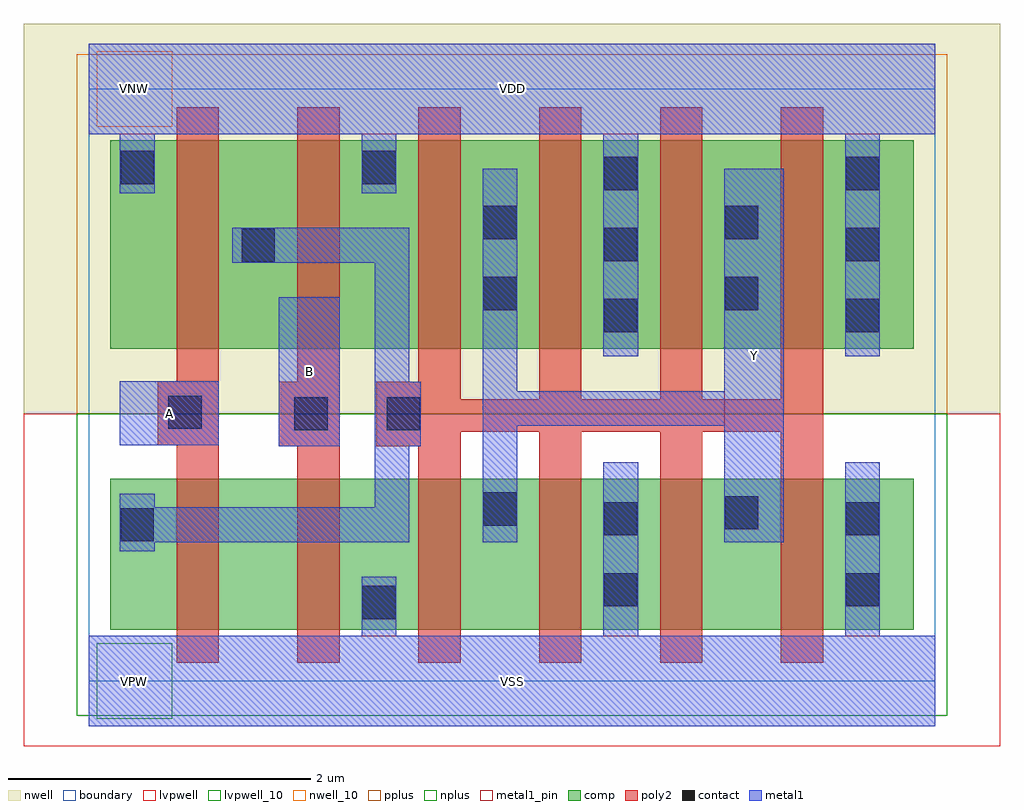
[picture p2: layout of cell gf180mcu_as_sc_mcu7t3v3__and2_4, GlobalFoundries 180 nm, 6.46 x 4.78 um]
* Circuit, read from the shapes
.subckt gf180mcu_as_sc_mcu7t3v3__and2_4 A B VDD VNW VSS Y
XM1 n1 A n2 VSUBS nfet_03v3 w=1u l=0.28u
XM2 VSS B n1 VSUBS nfet_03v3 w=1u l=0.28u
XM3 Y n2 VSS VSUBS nfet_03v3 w=1u l=0.28u m=4
XM4 n2 A VDD VNW pfet_03v3 w=1.38u l=0.28u
XM5 VDD B n2 VNW pfet_03v3 w=1.38u l=0.28u
XM6 Y n2 VDD VNW pfet_03v3 w=1.38u l=0.28u m=4
.ends

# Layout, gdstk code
import gdstk
lib = gdstk.Library(unit=1e-6, precision=1e-09)
def R(c, l, rs):  # rectangles x0, y0, x1, y1
    for r in rs: c.add(gdstk.rectangle(r[:2], r[2:], *l))
boundary = (0, 0)
nwell = (21, 0)
nwell_10 = (21, 10)
comp = (22, 0)
poly2 = (30, 0)
pplus = (31, 0)
nplus = (32, 0)
contact = (33, 0)
metal1 = (34, 0)
metal1_pin = (34, 10)
lvpwell = (204, 0)
lvpwell_10 = (204, 10)

gf180mcu_as_sc_mcu7t3v3_ = lib.new_cell('gf180mcu_as_sc_mcu7t3v3__and2_4')
R(gf180mcu_as_sc_mcu7t3v3_, boundary, [(0,0,5.6,3.92), (0,0,5.6,3.92)])
R(gf180mcu_as_sc_mcu7t3v3_, nwell, [(-0.43,1.77,6.03,4.35), (-0.43,1.77,6.03,4.35)])
R(gf180mcu_as_sc_mcu7t3v3_, nwell_10, [(0.05,3.67,0.55,4.17), (0.05,3.67,0.55,4.17)])
R(gf180mcu_as_sc_mcu7t3v3_, comp, [(0.14,0.34,5.46,1.34), (0.14,0.34,5.46,1.34), (0.14,2.2,5.46,3.58), (0.14,2.2,5.46,3.58)])
R(gf180mcu_as_sc_mcu7t3v3_, poly2, [(0.58,0.12,0.86,1.56), (0.58,0.12,0.86,1.56), (1.38,0.12,1.66,1.555), (1.38,0.12,1.66,1.555), (2.18,0.12,2.46,1.555), (2.18,0.12,2.46,1.555), (2.98,0.12,3.26,1.65), (2.98,0.12,3.26,1.65), (3.78,0.12,4.06,1.65), (3.78,0.12,4.06,1.65), (4.58,0.12,4.86,1.65), (4.58,0.12,4.86,1.65), (1.255,1.555,1.66,1.98), (1.255,1.555,1.66,1.98), (1.9,1.555,2.46,1.65), (1.9,1.555,2.46,1.65), (0.455,1.56,0.86,1.985), (0.455,1.56,0.86,1.985), (1.9,1.65,4.86,1.865), (1.9,1.65,4.86,1.865), (1.9,1.865,2.46,1.98), (1.9,1.865,2.46,1.98), (2.98,1.865,3.26,3.8), (2.98,1.865,3.26,3.8), (3.78,1.865,4.06,3.8), (3.78,1.865,4.06,3.8), (4.58,1.865,4.86,3.8), (4.58,1.865,4.86,3.8), (1.38,1.98,1.66,3.8), (1.38,1.98,1.66,3.8), (2.18,1.98,2.46,3.8), (2.18,1.98,2.46,3.8), (0.58,1.985,0.86,3.8), (0.58,1.985,0.86,3.8)])
R(gf180mcu_as_sc_mcu7t3v3_, pplus, [(-0.08,1.77,5.68,4.15), (-0.08,1.77,5.68,4.15), (0.35,1.97,5.09,2.04), (0.35,1.97,5.09,2.04), (-0.02,2.04,5.62,3.74), (-0.02,2.04,5.62,3.74), (0.35,3.74,5.09,3.81), (0.35,3.74,5.09,3.81)])
R(gf180mcu_as_sc_mcu7t3v3_, nplus, [(-0.08,-0.23,5.68,1.77), (-0.08,-0.23,5.68,1.77), (-0.08,-0.23,5.68,1.77), (-0.08,-0.23,5.68,1.77)])
R(gf180mcu_as_sc_mcu7t3v3_, contact, [(1.81,0.41,2.03,0.63), (1.81,0.41,2.03,0.63), (3.41,0.495,3.63,0.715), (3.41,0.495,3.63,0.715), (5.01,0.495,5.23,0.715), (5.01,0.495,5.23,0.715), (0.21,0.925,0.43,1.145), (0.21,0.925,0.43,1.145), (3.41,0.965,3.63,1.185), (3.41,0.965,3.63,1.185), (5.01,0.965,5.23,1.185), (5.01,0.965,5.23,1.185), (4.21,1.005,4.43,1.225), (4.21,1.005,4.43,1.225), (2.61,1.03,2.83,1.25), (2.61,1.03,2.83,1.25), (1.36,1.66,1.58,1.88), (1.36,1.66,1.58,1.88), (1.97,1.66,2.19,1.88), (1.97,1.66,2.19,1.88), (0.525,1.67,0.745,1.89), (0.525,1.67,0.745,1.89), (3.41,2.31,3.63,2.53), (3.41,2.31,3.63,2.53), (5.01,2.31,5.23,2.53), (5.01,2.31,5.23,2.53), (2.61,2.455,2.83,2.675), (2.61,2.455,2.83,2.675), (4.21,2.455,4.43,2.675), (4.21,2.455,4.43,2.675), (1.01,2.775,1.23,2.995), (1.01,2.775,1.23,2.995), (3.41,2.78,3.63,3), (3.41,2.78,3.63,3), (5.01,2.78,5.23,3), (5.01,2.78,5.23,3), (2.61,2.925,2.83,3.145), (2.61,2.925,2.83,3.145), (4.21,2.925,4.43,3.145), (4.21,2.925,4.43,3.145), (3.41,3.25,3.63,3.47), (3.41,3.25,3.63,3.47), (5.01,3.25,5.23,3.47), (5.01,3.25,5.23,3.47), (0.21,3.29,0.43,3.51), (0.21,3.29,0.43,3.51), (1.81,3.29,2.03,3.51), (1.81,3.29,2.03,3.51)])
R(gf180mcu_as_sc_mcu7t3v3_, metal1, [(0,-0.3,5.6,0.3), (0,-0.3,5.6,0.3), (1.805,0.3,2.035,0.69), (1.805,0.3,2.035,0.69), (3.405,0.3,3.635,1.45), (3.405,0.3,3.635,1.45), (5.005,0.3,5.235,1.45), (5.005,0.3,5.235,1.45), (0.205,0.86,0.435,0.92), (0.205,0.86,0.435,0.92), (0.205,0.92,2.12,1.15), (0.205,0.92,2.12,1.15), (2.605,0.92,2.835,1.69), (2.605,0.92,2.835,1.69), (4.205,0.92,4.6,1.69), (4.205,0.92,4.6,1.69), (0.205,1.15,0.435,1.24), (0.205,1.15,0.435,1.24), (1.89,1.15,2.12,1.555), (1.89,1.15,2.12,1.555), (1.255,1.555,1.66,2.54), (1.255,1.555,1.66,2.54), (1.89,1.555,2.195,1.98), (1.89,1.555,2.195,1.98), (0.205,1.56,0.86,1.985), (0.205,1.56,0.86,1.985), (2.605,1.69,4.6,1.92), (2.605,1.69,4.6,1.92), (2.605,1.92,2.835,3.39), (2.605,1.92,2.835,3.39), (4.205,1.92,4.6,3.39), (4.205,1.92,4.6,3.39), (1.89,1.98,2.12,2.77), (1.89,1.98,2.12,2.77), (3.405,2.15,3.635,3.62), (3.405,2.15,3.635,3.62), (5.005,2.15,5.235,3.62), (5.005,2.15,5.235,3.62), (0.95,2.77,2.12,3), (0.95,2.77,2.12,3), (0.205,3.23,0.435,3.62), (0.205,3.23,0.435,3.62), (1.805,3.23,2.035,3.62), (1.805,3.23,2.035,3.62), (0,3.62,5.6,4.22), (0,3.62,5.6,4.22)])
R(gf180mcu_as_sc_mcu7t3v3_, metal1_pin, [(0,-0.3,5.6,0.3), (0,-0.3,5.6,0.3), (4.205,0.92,4.6,3.39), (4.205,0.92,4.6,3.39), (1.255,1.555,1.66,2.54), (1.255,1.555,1.66,2.54), (0.205,1.56,0.86,1.985), (0.205,1.56,0.86,1.985), (0,3.62,5.6,4.22), (0,3.62,5.6,4.22)])
R(gf180mcu_as_sc_mcu7t3v3_, lvpwell, [(-0.43,-0.43,6.03,1.77), (-0.43,-0.43,6.03,1.77)])
R(gf180mcu_as_sc_mcu7t3v3_, lvpwell_10, [(0.05,-0.25,0.55,0.25), (0.05,-0.25,0.55,0.25)])
gf180mcu_as_sc_mcu7t3v3_.add(gdstk.Label('VDD', (2.8,3.92), layer=34, texttype=10))
gf180mcu_as_sc_mcu7t3v3_.add(gdstk.Label('VSS', (2.8,0), layer=34, texttype=10))
gf180mcu_as_sc_mcu7t3v3_.add(gdstk.Label('B', (1.457,2.047), layer=34, texttype=10))
gf180mcu_as_sc_mcu7t3v3_.add(gdstk.Label('A', (0.532,1.772), layer=34, texttype=10))
gf180mcu_as_sc_mcu7t3v3_.add(gdstk.Label('Y', (4.402,2.155), layer=34, texttype=10))
gf180mcu_as_sc_mcu7t3v3_.add(gdstk.Label('VDD', (2.8,3.92), layer=34, texttype=10))
gf180mcu_as_sc_mcu7t3v3_.add(gdstk.Label('VSS', (2.8,0), layer=34, texttype=10))
gf180mcu_as_sc_mcu7t3v3_.add(gdstk.Label('B', (1.457,2.047), layer=34, texttype=10))
gf180mcu_as_sc_mcu7t3v3_.add(gdstk.Label('A', (0.532,1.772), layer=34, texttype=10))
gf180mcu_as_sc_mcu7t3v3_.add(gdstk.Label('Y', (4.402,2.155), layer=34, texttype=10))
gf180mcu_as_sc_mcu7t3v3_.add(gdstk.Label('VNW', (0.3,3.92), layer=21, texttype=10))
gf180mcu_as_sc_mcu7t3v3_.add(gdstk.Label('VNW', (0.3,3.92), layer=21, texttype=10))
gf180mcu_as_sc_mcu7t3v3_.add(gdstk.Label('VPW', (0.3,0), layer=204, texttype=10))
gf180mcu_as_sc_mcu7t3v3_.add(gdstk.Label('VPW', (0.3,0), layer=204, texttype=10))

lib.write_gds('gf180mcu_as_sc_mcu7t3v3__and2_4.gds')
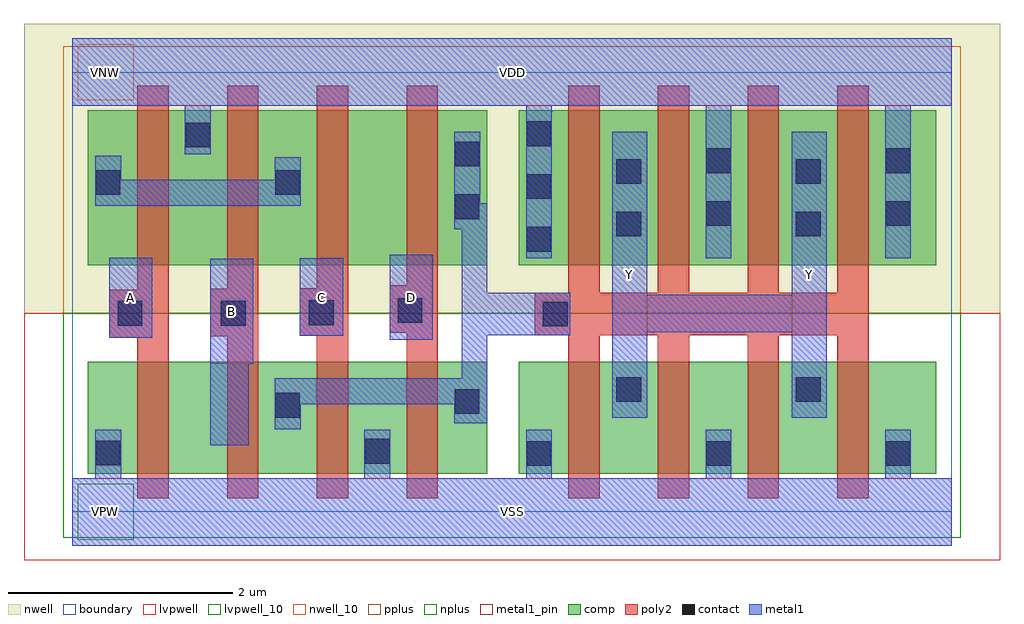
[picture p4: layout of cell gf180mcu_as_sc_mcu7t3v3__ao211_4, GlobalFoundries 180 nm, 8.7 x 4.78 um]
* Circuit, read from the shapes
.subckt gf180mcu_as_sc_mcu7t3v3__ao211_4 A B C D VDD VNW VSS Y
XM1 n1 A VSS VSUBS nfet_03v3 w=1u l=0.28u
XM2 n2 B n1 VSUBS nfet_03v3 w=1u l=0.28u
XM3 VSS C n2 VSUBS nfet_03v3 w=1u l=0.28u
XM4 n2 D VSS VSUBS nfet_03v3 w=1u l=0.28u
XM5 Y n2 VSS VSUBS nfet_03v3 w=1u l=0.28u m=4
XM6 VDD A n3 VNW pfet_03v3 w=1.38u l=0.28u
XM7 n3 B VDD VNW pfet_03v3 w=1.38u l=0.28u
XM8 n4 C n3 VNW pfet_03v3 w=1.38u l=0.28u
XM9 n2 D n4 VNW pfet_03v3 w=1.38u l=0.28u
XM10 Y n2 VDD VNW pfet_03v3 w=1.38u l=0.28u m=4
.ends

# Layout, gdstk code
import gdstk
lib = gdstk.Library(unit=1e-6, precision=1e-09)
def R(c, l, rs):  # rectangles x0, y0, x1, y1
    for r in rs: c.add(gdstk.rectangle(r[:2], r[2:], *l))
boundary = (0, 0)
nwell = (21, 0)
nwell_10 = (21, 10)
comp = (22, 0)
poly2 = (30, 0)
pplus = (31, 0)
nplus = (32, 0)
contact = (33, 0)
metal1 = (34, 0)
metal1_pin = (34, 10)
lvpwell = (204, 0)
lvpwell_10 = (204, 10)

gf180mcu_as_sc_mcu7t3v3_ = lib.new_cell('gf180mcu_as_sc_mcu7t3v3__ao211_4')
R(gf180mcu_as_sc_mcu7t3v3_, boundary, [(0,0,7.84,3.92), (0,0,7.84,3.92)])
R(gf180mcu_as_sc_mcu7t3v3_, nwell, [(-0.43,1.77,8.27,4.35), (-0.43,1.77,8.27,4.35)])
R(gf180mcu_as_sc_mcu7t3v3_, nwell_10, [(0.05,3.67,0.55,4.17), (0.05,3.67,0.55,4.17)])
R(gf180mcu_as_sc_mcu7t3v3_, comp, [(0.14,0.34,3.7,1.34), (0.14,0.34,3.7,1.34), (3.98,0.34,7.7,1.34), (3.98,0.34,7.7,1.34), (0.14,2.2,3.7,3.58), (0.14,2.2,3.7,3.58), (3.98,2.2,7.7,3.58), (3.98,2.2,7.7,3.58)])
R(gf180mcu_as_sc_mcu7t3v3_, poly2, [(0.58,0.12,0.86,1.55), (0.58,0.12,0.86,1.55), (1.38,0.12,1.66,1.565), (1.38,0.12,1.66,1.565), (2.18,0.12,2.46,1.57), (2.18,0.12,2.46,1.57), (2.98,0.12,3.26,1.595), (2.98,0.12,3.26,1.595), (4.42,0.12,4.7,1.575), (4.42,0.12,4.7,1.575), (5.22,0.12,5.5,1.575), (5.22,0.12,5.5,1.575), (6.02,0.12,6.3,1.575), (6.02,0.12,6.3,1.575), (6.82,0.12,7.1,1.575), (6.82,0.12,7.1,1.575), (0.33,1.55,0.86,1.98), (0.33,1.55,0.86,1.98), (1.23,1.565,1.66,1.99), (1.23,1.565,1.66,1.99), (2.03,1.57,2.46,1.995), (2.03,1.57,2.46,1.995), (4.125,1.575,7.1,1.955), (4.125,1.575,7.1,1.955), (2.83,1.595,3.26,2.02), (2.83,1.595,3.26,2.02), (4.42,1.955,4.7,3.8), (4.42,1.955,4.7,3.8), (5.22,1.955,5.5,3.8), (5.22,1.955,5.5,3.8), (6.02,1.955,6.3,3.8), (6.02,1.955,6.3,3.8), (6.82,1.955,7.1,3.8), (6.82,1.955,7.1,3.8), (0.58,1.98,0.86,3.8), (0.58,1.98,0.86,3.8), (1.38,1.99,1.66,3.8), (1.38,1.99,1.66,3.8), (2.18,1.995,2.46,3.8), (2.18,1.995,2.46,3.8), (2.98,2.02,3.26,3.8), (2.98,2.02,3.26,3.8)])
R(gf180mcu_as_sc_mcu7t3v3_, pplus, [(-0.08,1.77,7.92,4.15), (-0.08,1.77,7.92,4.15), (0.35,1.97,3.49,2.04), (0.35,1.97,3.49,2.04), (4.19,1.97,7.33,2.04), (4.19,1.97,7.33,2.04), (-0.02,2.04,7.86,3.74), (-0.02,2.04,7.86,3.74), (0.35,3.74,3.49,3.81), (0.35,3.74,3.49,3.81), (4.19,3.74,7.33,3.81), (4.19,3.74,7.33,3.81)])
R(gf180mcu_as_sc_mcu7t3v3_, nplus, [(-0.08,-0.23,7.92,1.77), (-0.08,-0.23,7.92,1.77), (-0.08,-0.23,7.92,1.77), (-0.08,-0.23,7.92,1.77)])
R(gf180mcu_as_sc_mcu7t3v3_, contact, [(4.05,0.41,4.27,0.63), (4.05,0.41,4.27,0.63), (5.65,0.41,5.87,0.63), (5.65,0.41,5.87,0.63), (7.25,0.41,7.47,0.63), (7.25,0.41,7.47,0.63), (0.21,0.415,0.43,0.635), (0.21,0.415,0.43,0.635), (2.61,0.43,2.83,0.65), (2.61,0.43,2.83,0.65), (1.81,0.84,2.03,1.06), (1.81,0.84,2.03,1.06), (3.41,0.875,3.63,1.095), (3.41,0.875,3.63,1.095), (4.85,0.98,5.07,1.2), (4.85,0.98,5.07,1.2), (6.45,0.98,6.67,1.2), (6.45,0.98,6.67,1.2), (4.195,1.655,4.415,1.875), (4.195,1.655,4.415,1.875), (0.405,1.66,0.625,1.88), (0.405,1.66,0.625,1.88), (1.325,1.66,1.545,1.88), (1.325,1.66,1.545,1.88), (2.11,1.665,2.33,1.885), (2.11,1.665,2.33,1.885), (2.9,1.685,3.12,1.905), (2.9,1.685,3.12,1.905), (4.05,2.32,4.27,2.54), (4.05,2.32,4.27,2.54), (4.85,2.455,5.07,2.675), (4.85,2.455,5.07,2.675), (6.45,2.455,6.67,2.675), (6.45,2.455,6.67,2.675), (5.65,2.55,5.87,2.77), (5.65,2.55,5.87,2.77), (7.25,2.55,7.47,2.77), (7.25,2.55,7.47,2.77), (3.41,2.61,3.63,2.83), (3.41,2.61,3.63,2.83), (4.05,2.79,4.27,3.01), (4.05,2.79,4.27,3.01), (0.21,2.825,0.43,3.045), (0.21,2.825,0.43,3.045), (1.81,2.825,2.03,3.045), (1.81,2.825,2.03,3.045), (4.85,2.925,5.07,3.145), (4.85,2.925,5.07,3.145), (6.45,2.925,6.67,3.145), (6.45,2.925,6.67,3.145), (5.65,3.02,5.87,3.24), (5.65,3.02,5.87,3.24), (7.25,3.02,7.47,3.24), (7.25,3.02,7.47,3.24), (3.41,3.08,3.63,3.3), (3.41,3.08,3.63,3.3), (1.01,3.25,1.23,3.47), (1.01,3.25,1.23,3.47), (4.05,3.26,4.27,3.48), (4.05,3.26,4.27,3.48)])
R(gf180mcu_as_sc_mcu7t3v3_, metal1, [(0,-0.3,7.84,0.3), (0,-0.3,7.84,0.3), (0.205,0.3,0.435,0.73), (0.205,0.3,0.435,0.73), (2.605,0.3,2.835,0.73), (2.605,0.3,2.835,0.73), (4.045,0.3,4.275,0.73), (4.045,0.3,4.275,0.73), (5.645,0.3,5.875,0.73), (5.645,0.3,5.875,0.73), (7.245,0.3,7.475,0.73), (7.245,0.3,7.475,0.73), (1.23,0.595,1.575,1.32), (1.23,0.595,1.575,1.32), (1.805,0.735,2.035,0.96), (1.805,0.735,2.035,0.96), (3.405,0.79,3.7,0.96), (3.405,0.79,3.7,0.96), (4.815,0.84,5.125,1.6), (4.815,0.84,5.125,1.6), (6.415,0.84,6.725,1.6), (6.415,0.84,6.725,1.6), (1.805,0.96,3.7,1.19), (1.805,0.96,3.7,1.19), (3.47,1.19,3.7,1.575), (3.47,1.19,3.7,1.575), (1.23,1.32,1.615,2.255), (1.23,1.32,1.615,2.255), (2.83,1.535,3.215,2.29), (2.83,1.535,3.215,2.29), (0.33,1.55,0.715,2.265), (0.33,1.55,0.715,2.265), (2.03,1.57,2.415,2.26), (2.03,1.57,2.415,2.26), (3.47,1.575,4.44,1.955), (3.47,1.575,4.44,1.955), (4.815,1.6,6.725,1.935), (4.815,1.6,6.725,1.935), (4.815,1.935,5.125,3.39), (4.815,1.935,5.125,3.39), (6.415,1.935,6.725,3.39), (6.415,1.935,6.725,3.39), (3.47,1.955,3.7,2.52), (3.47,1.955,3.7,2.52), (4.045,2.26,4.275,3.62), (4.045,2.26,4.275,3.62), (5.645,2.26,5.875,3.62), (5.645,2.26,5.875,3.62), (7.245,2.26,7.475,3.62), (7.245,2.26,7.475,3.62), (3.405,2.52,3.7,2.75), (3.405,2.52,3.7,2.75), (0.205,2.73,2.035,2.96), (0.205,2.73,2.035,2.96), (3.405,2.75,3.635,3.39), (3.405,2.75,3.635,3.39), (0.205,2.96,0.435,3.175), (0.205,2.96,0.435,3.175), (1.805,2.96,2.035,3.16), (1.805,2.96,2.035,3.16), (1.005,3.19,1.235,3.62), (1.005,3.19,1.235,3.62), (0,3.62,7.84,4.22), (0,3.62,7.84,4.22)])
R(gf180mcu_as_sc_mcu7t3v3_, metal1_pin, [(0,-0.3,7.84,0.3), (0,-0.3,7.84,0.3), (4.815,0.84,5.125,3.39), (4.815,0.84,5.125,3.39), (6.415,0.84,6.725,3.39), (6.415,0.84,6.725,3.39), (1.23,1.32,1.615,2.255), (1.23,1.32,1.615,2.255), (2.83,1.535,3.215,2.29), (2.83,1.535,3.215,2.29), (0.33,1.55,0.715,2.265), (0.33,1.55,0.715,2.265), (2.03,1.57,2.415,2.26), (2.03,1.57,2.415,2.26), (0,3.62,7.84,4.22), (0,3.62,7.84,4.22)])
R(gf180mcu_as_sc_mcu7t3v3_, lvpwell, [(-0.43,-0.43,8.27,1.77), (-0.43,-0.43,8.27,1.77)])
R(gf180mcu_as_sc_mcu7t3v3_, lvpwell_10, [(0.05,-0.25,0.55,0.25), (0.05,-0.25,0.55,0.25)])
gf180mcu_as_sc_mcu7t3v3_.add(gdstk.Label('VDD', (3.92,3.92), layer=34, texttype=10))
gf180mcu_as_sc_mcu7t3v3_.add(gdstk.Label('VSS', (3.92,0), layer=34, texttype=10))
gf180mcu_as_sc_mcu7t3v3_.add(gdstk.Label('A', (0.522,1.907), layer=34, texttype=10))
gf180mcu_as_sc_mcu7t3v3_.add(gdstk.Label('B', (1.422,1.787), layer=34, texttype=10))
gf180mcu_as_sc_mcu7t3v3_.add(gdstk.Label('C', (2.222,1.915), layer=34, texttype=10))
gf180mcu_as_sc_mcu7t3v3_.add(gdstk.Label('D', (3.022,1.912), layer=34, texttype=10))
gf180mcu_as_sc_mcu7t3v3_.add(gdstk.Label('Y', (6.57,2.115), layer=34, texttype=10))
gf180mcu_as_sc_mcu7t3v3_.add(gdstk.Label('Y', (4.97,2.115), layer=34, texttype=10))
gf180mcu_as_sc_mcu7t3v3_.add(gdstk.Label('VDD', (3.92,3.92), layer=34, texttype=10))
gf180mcu_as_sc_mcu7t3v3_.add(gdstk.Label('VSS', (3.92,0), layer=34, texttype=10))
gf180mcu_as_sc_mcu7t3v3_.add(gdstk.Label('A', (0.522,1.907), layer=34, texttype=10))
gf180mcu_as_sc_mcu7t3v3_.add(gdstk.Label('B', (1.422,1.787), layer=34, texttype=10))
gf180mcu_as_sc_mcu7t3v3_.add(gdstk.Label('C', (2.222,1.915), layer=34, texttype=10))
gf180mcu_as_sc_mcu7t3v3_.add(gdstk.Label('D', (3.022,1.912), layer=34, texttype=10))
gf180mcu_as_sc_mcu7t3v3_.add(gdstk.Label('Y', (6.57,2.115), layer=34, texttype=10))
gf180mcu_as_sc_mcu7t3v3_.add(gdstk.Label('Y', (4.97,2.115), layer=34, texttype=10))
gf180mcu_as_sc_mcu7t3v3_.add(gdstk.Label('VNW', (0.3,3.92), layer=21, texttype=10))
gf180mcu_as_sc_mcu7t3v3_.add(gdstk.Label('VNW', (0.3,3.92), layer=21, texttype=10))
gf180mcu_as_sc_mcu7t3v3_.add(gdstk.Label('VPW', (0.3,0), layer=204, texttype=10))
gf180mcu_as_sc_mcu7t3v3_.add(gdstk.Label('VPW', (0.3,0), layer=204, texttype=10))

lib.write_gds('gf180mcu_as_sc_mcu7t3v3__ao211_4.gds')
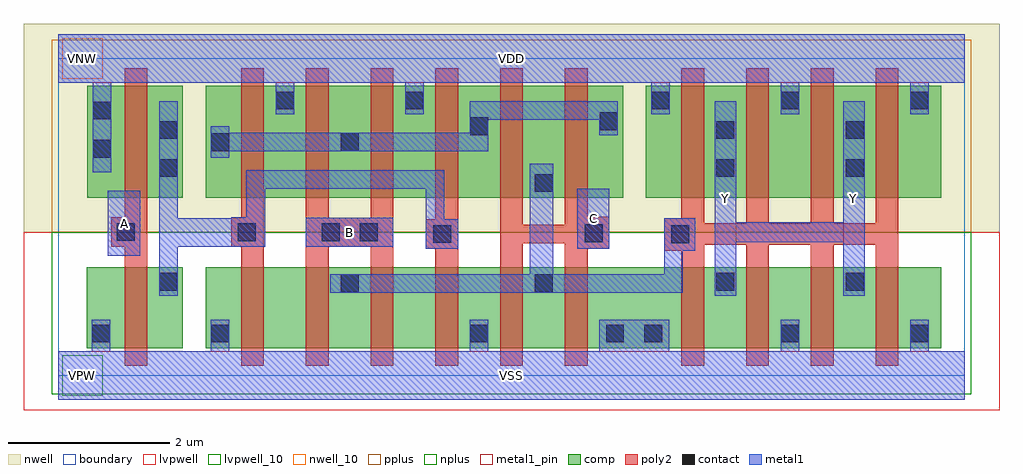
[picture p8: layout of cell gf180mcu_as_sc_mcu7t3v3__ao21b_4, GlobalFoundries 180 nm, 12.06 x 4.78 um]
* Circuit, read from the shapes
.subckt gf180mcu_as_sc_mcu7t3v3__ao21b_4 A B C VDD VNW VSS Y
XM1 n1 A VSS VSUBS nfet_03v3 w=1u l=0.28u
XM2 n2 n1 VSS VSUBS nfet_03v3 w=1u l=0.28u
XM3 n3 B n2 VSUBS nfet_03v3 w=1u l=0.28u
XM4 n4 B n3 VSUBS nfet_03v3 w=1u l=0.28u
XM5 VSS n1 n4 VSUBS nfet_03v3 w=1u l=0.28u
XM6 n3 C VSS VSUBS nfet_03v3 w=1u l=0.28u m=2
XM7 Y n3 VSS VSUBS nfet_03v3 w=1u l=0.28u m=4
XM8 n1 A VDD VNW pfet_03v3 w=1.38u l=0.28u
XM9 VDD n1 n5 VNW pfet_03v3 w=1.38u l=0.28u m=2
XM10 n5 B VDD VNW pfet_03v3 w=1.38u l=0.28u m=2
XM11 n3 C n5 VNW pfet_03v3 w=1.38u l=0.28u m=2
XM12 Y n3 VDD VNW pfet_03v3 w=1.38u l=0.28u m=4
.ends

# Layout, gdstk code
import gdstk
lib = gdstk.Library(unit=1e-6, precision=1e-09)
def R(c, l, rs):  # rectangles x0, y0, x1, y1
    for r in rs: c.add(gdstk.rectangle(r[:2], r[2:], *l))
boundary = (0, 0)
nwell = (21, 0)
nwell_10 = (21, 10)
comp = (22, 0)
poly2 = (30, 0)
pplus = (31, 0)
nplus = (32, 0)
contact = (33, 0)
metal1 = (34, 0)
metal1_pin = (34, 10)
lvpwell = (204, 0)
lvpwell_10 = (204, 10)

gf180mcu_as_sc_mcu7t3v3_ = lib.new_cell('gf180mcu_as_sc_mcu7t3v3__ao21b_4')
R(gf180mcu_as_sc_mcu7t3v3_, boundary, [(0,0,11.2,3.92), (0,0,11.2,3.92)])
R(gf180mcu_as_sc_mcu7t3v3_, nwell, [(-0.43,1.77,11.63,4.35), (-0.43,1.77,11.63,4.35)])
R(gf180mcu_as_sc_mcu7t3v3_, nwell_10, [(0.05,3.67,0.55,4.17), (0.05,3.67,0.55,4.17)])
R(gf180mcu_as_sc_mcu7t3v3_, comp, [(0.35,0.34,1.54,1.34), (0.35,0.34,1.54,1.34), (1.82,0.34,10.91,1.34), (1.82,0.34,10.91,1.34), (0.36,2.2,1.54,3.58), (0.36,2.2,1.54,3.58), (1.82,2.2,6.98,3.58), (1.82,2.2,6.98,3.58), (7.26,2.2,10.91,3.58), (7.26,2.2,10.91,3.58)])
R(gf180mcu_as_sc_mcu7t3v3_, poly2, [(0.82,0.12,1.1,1.595), (0.82,0.12,1.1,1.595), (2.26,0.12,2.54,1.59), (2.26,0.12,2.54,1.59), (3.06,0.12,3.34,1.59), (3.06,0.12,3.34,1.59), (3.86,0.12,4.14,1.59), (3.86,0.12,4.14,1.59), (4.66,0.12,4.94,1.57), (4.66,0.12,4.94,1.57), (5.46,0.12,5.74,1.635), (5.46,0.12,5.74,1.635), (6.26,0.12,6.54,1.565), (6.26,0.12,6.54,1.565), (7.7,0.12,7.98,1.545), (7.7,0.12,7.98,1.545), (8.5,0.12,8.78,1.62), (8.5,0.12,8.78,1.62), (9.3,0.12,9.58,1.62), (9.3,0.12,9.58,1.62), (10.1,0.12,10.38,1.62), (10.1,0.12,10.38,1.62), (7.485,1.545,7.98,1.62), (7.485,1.545,7.98,1.62), (6.26,1.565,6.805,1.635), (6.26,1.565,6.805,1.635), (4.54,1.57,4.945,1.93), (4.54,1.57,4.945,1.93), (2.135,1.59,2.54,1.95), (2.135,1.59,2.54,1.95), (3.06,1.59,4.14,1.95), (3.06,1.59,4.14,1.95), (0.655,1.595,1.1,1.955), (0.655,1.595,1.1,1.955), (7.485,1.62,10.38,1.885), (7.485,1.62,10.38,1.885), (5.46,1.635,6.805,1.865), (5.46,1.635,6.805,1.865), (5.46,1.865,5.74,3.8), (5.46,1.865,5.74,3.8), (6.26,1.865,6.805,1.96), (6.26,1.865,6.805,1.96), (7.485,1.885,7.98,1.945), (7.485,1.885,7.98,1.945), (8.5,1.885,8.78,3.8), (8.5,1.885,8.78,3.8), (9.3,1.885,9.58,3.8), (9.3,1.885,9.58,3.8), (10.1,1.885,10.38,3.8), (10.1,1.885,10.38,3.8), (4.66,1.93,4.94,3.8), (4.66,1.93,4.94,3.8), (7.7,1.945,7.98,3.8), (7.7,1.945,7.98,3.8), (2.26,1.95,2.54,3.8), (2.26,1.95,2.54,3.8), (3.06,1.95,3.34,3.8), (3.06,1.95,3.34,3.8), (3.86,1.95,4.14,3.8), (3.86,1.95,4.14,3.8), (0.82,1.955,1.1,3.8), (0.82,1.955,1.1,3.8), (6.26,1.96,6.54,3.8), (6.26,1.96,6.54,3.8)])
R(gf180mcu_as_sc_mcu7t3v3_, pplus, [(-0.08,1.77,11.28,4.15), (-0.08,1.77,11.28,4.15), (0.59,1.97,1.33,2.04), (0.59,1.97,1.33,2.04), (2.03,1.97,6.77,2.04), (2.03,1.97,6.77,2.04), (7.47,1.97,10.61,2.04), (7.47,1.97,10.61,2.04), (0.2,2.04,11.07,3.74), (0.2,2.04,11.07,3.74), (0.59,3.74,1.33,3.81), (0.59,3.74,1.33,3.81), (2.03,3.74,6.77,3.81), (2.03,3.74,6.77,3.81), (7.47,3.74,10.61,3.81), (7.47,3.74,10.61,3.81)])
R(gf180mcu_as_sc_mcu7t3v3_, nplus, [(-0.08,-0.23,11.28,1.77), (-0.08,-0.23,11.28,1.77), (-0.08,-0.23,11.28,1.77), (-0.08,-0.23,11.28,1.77)])
R(gf180mcu_as_sc_mcu7t3v3_, contact, [(0.42,0.41,0.64,0.63), (0.42,0.41,0.64,0.63), (1.89,0.41,2.11,0.63), (1.89,0.41,2.11,0.63), (5.09,0.41,5.31,0.63), (5.09,0.41,5.31,0.63), (6.77,0.41,6.99,0.63), (6.77,0.41,6.99,0.63), (7.24,0.41,7.46,0.63), (7.24,0.41,7.46,0.63), (8.93,0.41,9.15,0.63), (8.93,0.41,9.15,0.63), (10.53,0.41,10.75,0.63), (10.53,0.41,10.75,0.63), (3.49,1.03,3.71,1.25), (3.49,1.03,3.71,1.25), (5.89,1.03,6.11,1.25), (5.89,1.03,6.11,1.25), (1.25,1.05,1.47,1.27), (1.25,1.05,1.47,1.27), (8.13,1.05,8.35,1.27), (8.13,1.05,8.35,1.27), (9.73,1.05,9.95,1.27), (9.73,1.05,9.95,1.27), (7.575,1.635,7.795,1.855), (7.575,1.635,7.795,1.855), (4.635,1.64,4.855,1.86), (4.635,1.64,4.855,1.86), (6.505,1.65,6.725,1.87), (6.505,1.65,6.725,1.87), (2.22,1.66,2.44,1.88), (2.22,1.66,2.44,1.88), (3.255,1.66,3.475,1.88), (3.255,1.66,3.475,1.88), (3.725,1.66,3.945,1.88), (3.725,1.66,3.945,1.88), (0.725,1.665,0.945,1.885), (0.725,1.665,0.945,1.885), (5.89,2.27,6.11,2.49), (5.89,2.27,6.11,2.49), (1.25,2.455,1.47,2.675), (1.25,2.455,1.47,2.675), (8.13,2.455,8.35,2.675), (8.13,2.455,8.35,2.675), (9.73,2.455,9.95,2.675), (9.73,2.455,9.95,2.675), (0.43,2.695,0.65,2.915), (0.43,2.695,0.65,2.915), (1.89,2.775,2.11,2.995), (1.89,2.775,2.11,2.995), (3.49,2.775,3.71,2.995), (3.49,2.775,3.71,2.995), (1.25,2.925,1.47,3.145), (1.25,2.925,1.47,3.145), (8.13,2.925,8.35,3.145), (8.13,2.925,8.35,3.145), (9.73,2.925,9.95,3.145), (9.73,2.925,9.95,3.145), (5.09,2.97,5.31,3.19), (5.09,2.97,5.31,3.19), (6.69,3.035,6.91,3.255), (6.69,3.035,6.91,3.255), (0.43,3.165,0.65,3.385), (0.43,3.165,0.65,3.385), (2.69,3.29,2.91,3.51), (2.69,3.29,2.91,3.51), (4.29,3.29,4.51,3.51), (4.29,3.29,4.51,3.51), (7.33,3.29,7.55,3.51), (7.33,3.29,7.55,3.51), (8.93,3.29,9.15,3.51), (8.93,3.29,9.15,3.51), (10.53,3.29,10.75,3.51), (10.53,3.29,10.75,3.51)])
R(gf180mcu_as_sc_mcu7t3v3_, metal1, [(0,-0.3,11.2,0.3), (0,-0.3,11.2,0.3), (0.415,0.3,0.645,0.69), (0.415,0.3,0.645,0.69), (1.885,0.3,2.115,0.69), (1.885,0.3,2.115,0.69), (5.085,0.3,5.315,0.69), (5.085,0.3,5.315,0.69), (6.685,0.3,7.55,0.69), (6.685,0.3,7.55,0.69), (8.925,0.3,9.155,0.69), (8.925,0.3,9.155,0.69), (10.525,0.3,10.755,0.69), (10.525,0.3,10.755,0.69), (1.245,0.985,1.475,1.595), (1.245,0.985,1.475,1.595), (8.11,0.99,8.375,1.645), (8.11,0.99,8.375,1.645), (9.7,0.99,9.965,1.645), (9.7,0.99,9.965,1.645), (3.36,1.025,7.715,1.255), (3.36,1.025,7.715,1.255), (5.825,1.255,6.115,2.62), (5.825,1.255,6.115,2.62), (7.485,1.255,7.715,1.545), (7.485,1.255,7.715,1.545), (0.61,1.48,1.015,2.285), (0.61,1.48,1.015,2.285), (7.485,1.545,7.87,1.945), (7.485,1.545,7.87,1.945), (6.415,1.565,6.805,2.31), (6.415,1.565,6.805,2.31), (4.54,1.57,4.945,1.93), (4.54,1.57,4.945,1.93), (2.135,1.59,2.555,1.595), (2.135,1.59,2.555,1.595), (3.06,1.59,4.14,1.95), (3.06,1.59,4.14,1.95), (1.245,1.595,2.555,1.945), (1.245,1.595,2.555,1.945), (8.11,1.645,9.965,1.895), (8.11,1.645,9.965,1.895), (8.11,1.895,8.375,3.39), (8.11,1.895,8.375,3.39), (9.7,1.895,9.965,3.39), (9.7,1.895,9.965,3.39), (4.54,1.93,4.77,2.31), (4.54,1.93,4.77,2.31), (1.245,1.945,1.475,3.39), (1.245,1.945,1.475,3.39), (2.135,1.945,2.555,1.955), (2.135,1.945,2.555,1.955), (2.325,1.955,2.555,2.31), (2.325,1.955,2.555,2.31), (2.325,2.31,4.77,2.54), (2.325,2.31,4.77,2.54), (0.425,2.515,0.655,3.62), (0.425,2.515,0.655,3.62), (1.885,2.695,2.115,2.77), (1.885,2.695,2.115,2.77), (1.885,2.77,5.315,3), (1.885,2.77,5.315,3), (6.685,2.97,6.915,3.16), (6.685,2.97,6.915,3.16), (1.885,3,2.115,3.08), (1.885,3,2.115,3.08), (5.085,3,5.315,3.16), (5.085,3,5.315,3.16), (5.085,3.16,6.915,3.39), (5.085,3.16,6.915,3.39), (2.685,3.23,2.915,3.62), (2.685,3.23,2.915,3.62), (4.285,3.23,4.515,3.62), (4.285,3.23,4.515,3.62), (7.325,3.23,7.555,3.62), (7.325,3.23,7.555,3.62), (8.925,3.23,9.155,3.62), (8.925,3.23,9.155,3.62), (10.525,3.23,10.755,3.62), (10.525,3.23,10.755,3.62), (0,3.62,11.2,4.22), (0,3.62,11.2,4.22)])
R(gf180mcu_as_sc_mcu7t3v3_, metal1_pin, [(0,-0.3,11.2,0.3), (0,-0.3,11.2,0.3), (8.11,0.99,8.375,3.39), (8.11,0.99,8.375,3.39), (9.7,0.99,9.965,3.39), (9.7,0.99,9.965,3.39), (0.61,1.48,1.015,2.285), (0.61,1.48,1.015,2.285), (6.415,1.565,6.805,2.31), (6.415,1.565,6.805,2.31), (3.06,1.59,4.14,1.95), (3.06,1.59,4.14,1.95), (0,3.62,11.2,4.22), (0,3.62,11.2,4.22)])
R(gf180mcu_as_sc_mcu7t3v3_, lvpwell, [(-0.43,-0.43,11.63,1.77), (-0.43,-0.43,11.63,1.77)])
R(gf180mcu_as_sc_mcu7t3v3_, lvpwell_10, [(0.05,-0.25,0.55,0.25), (0.05,-0.25,0.55,0.25)])
gf180mcu_as_sc_mcu7t3v3_.add(gdstk.Label('VDD', (5.6,3.92), layer=34, texttype=10))
gf180mcu_as_sc_mcu7t3v3_.add(gdstk.Label('VSS', (5.6,0), layer=34, texttype=10))
gf180mcu_as_sc_mcu7t3v3_.add(gdstk.Label('Y', (9.832,2.19), layer=34, texttype=10))
gf180mcu_as_sc_mcu7t3v3_.add(gdstk.Label('Y', (8.242,2.19), layer=34, texttype=10))
gf180mcu_as_sc_mcu7t3v3_.add(gdstk.Label('C', (6.61,1.937), layer=34, texttype=10))
gf180mcu_as_sc_mcu7t3v3_.add(gdstk.Label('B', (3.6,1.77), layer=34, texttype=10))
gf180mcu_as_sc_mcu7t3v3_.add(gdstk.Label('A', (0.812,1.882), layer=34, texttype=10))
gf180mcu_as_sc_mcu7t3v3_.add(gdstk.Label('VDD', (5.6,3.92), layer=34, texttype=10))
gf180mcu_as_sc_mcu7t3v3_.add(gdstk.Label('VSS', (5.6,0), layer=34, texttype=10))
gf180mcu_as_sc_mcu7t3v3_.add(gdstk.Label('Y', (9.832,2.19), layer=34, texttype=10))
gf180mcu_as_sc_mcu7t3v3_.add(gdstk.Label('Y', (8.242,2.19), layer=34, texttype=10))
gf180mcu_as_sc_mcu7t3v3_.add(gdstk.Label('C', (6.61,1.937), layer=34, texttype=10))
gf180mcu_as_sc_mcu7t3v3_.add(gdstk.Label('B', (3.6,1.77), layer=34, texttype=10))
gf180mcu_as_sc_mcu7t3v3_.add(gdstk.Label('A', (0.812,1.882), layer=34, texttype=10))
gf180mcu_as_sc_mcu7t3v3_.add(gdstk.Label('VNW', (0.3,3.92), layer=21, texttype=10))
gf180mcu_as_sc_mcu7t3v3_.add(gdstk.Label('VNW', (0.3,3.92), layer=21, texttype=10))
gf180mcu_as_sc_mcu7t3v3_.add(gdstk.Label('VPW', (0.3,0), layer=204, texttype=10))
gf180mcu_as_sc_mcu7t3v3_.add(gdstk.Label('VPW', (0.3,0), layer=204, texttype=10))

lib.write_gds('gf180mcu_as_sc_mcu7t3v3__ao21b_4.gds')
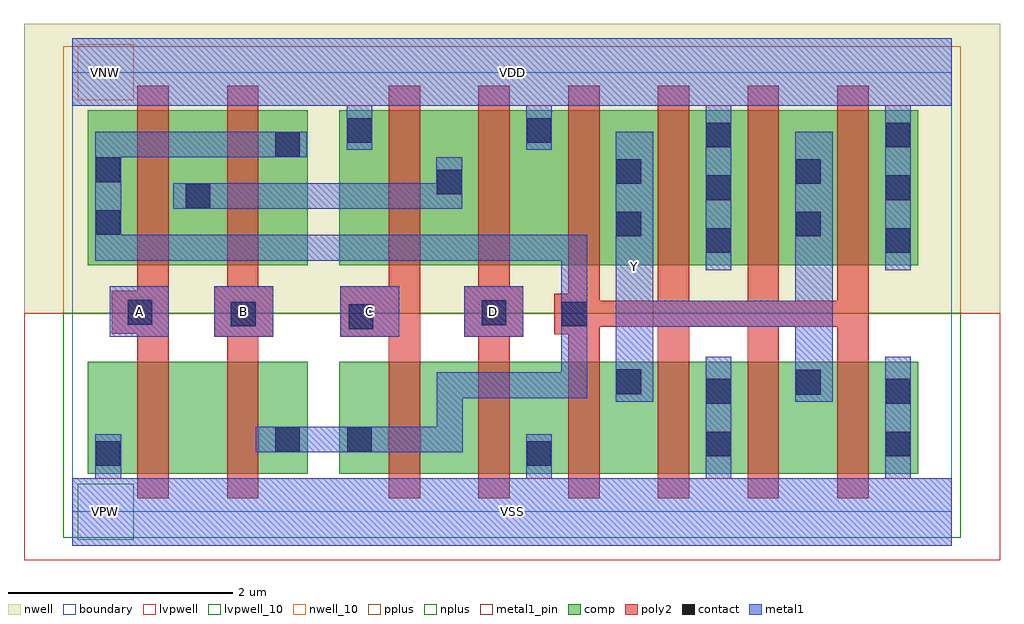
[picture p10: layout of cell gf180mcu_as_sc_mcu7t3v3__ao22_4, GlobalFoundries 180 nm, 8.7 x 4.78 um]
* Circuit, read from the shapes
.subckt gf180mcu_as_sc_mcu7t3v3__ao22_4 A B C D VDD VNW VSS Y
XM1 n1 A VSS VSUBS nfet_03v3 w=1u l=0.28u
XM2 n2 B n1 VSUBS nfet_03v3 w=1u l=0.28u
XM3 n3 C n2 VSUBS nfet_03v3 w=1u l=0.28u
XM4 VSS D n3 VSUBS nfet_03v3 w=1u l=0.28u
XM5 Y n2 VSS VSUBS nfet_03v3 w=1u l=0.28u m=4
XM6 n4 A n2 VNW pfet_03v3 w=1.38u l=0.28u
XM7 n2 B n4 VNW pfet_03v3 w=1.38u l=0.28u
XM8 n4 C VDD VNW pfet_03v3 w=1.38u l=0.28u
XM9 VDD D n4 VNW pfet_03v3 w=1.38u l=0.28u
XM10 Y n2 VDD VNW pfet_03v3 w=1.38u l=0.28u m=4
.ends

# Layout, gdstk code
import gdstk
lib = gdstk.Library(unit=1e-6, precision=1e-09)
def R(c, l, rs):  # rectangles x0, y0, x1, y1
    for r in rs: c.add(gdstk.rectangle(r[:2], r[2:], *l))
boundary = (0, 0)
nwell = (21, 0)
nwell_10 = (21, 10)
comp = (22, 0)
poly2 = (30, 0)
pplus = (31, 0)
nplus = (32, 0)
contact = (33, 0)
metal1 = (34, 0)
metal1_pin = (34, 10)
lvpwell = (204, 0)
lvpwell_10 = (204, 10)

gf180mcu_as_sc_mcu7t3v3_ = lib.new_cell('gf180mcu_as_sc_mcu7t3v3__ao22_4')
R(gf180mcu_as_sc_mcu7t3v3_, boundary, [(0,0,7.84,3.92), (0,0,7.84,3.92)])
R(gf180mcu_as_sc_mcu7t3v3_, nwell, [(-0.43,1.77,8.27,4.35), (-0.43,1.77,8.27,4.35)])
R(gf180mcu_as_sc_mcu7t3v3_, nwell_10, [(0.05,3.67,0.55,4.17), (0.05,3.67,0.55,4.17)])
R(gf180mcu_as_sc_mcu7t3v3_, comp, [(0.14,0.34,2.1,1.34), (0.14,0.34,2.1,1.34), (2.38,0.34,7.54,1.34), (2.38,0.34,7.54,1.34), (0.14,2.2,2.1,3.58), (0.14,2.2,2.1,3.58), (2.38,2.2,7.54,3.58), (2.38,2.2,7.54,3.58)])
R(gf180mcu_as_sc_mcu7t3v3_, poly2, [(0.58,0.12,0.86,1.59), (0.58,0.12,0.86,1.59), (1.38,0.12,1.66,1.56), (1.38,0.12,1.66,1.56), (2.82,0.12,3.1,1.56), (2.82,0.12,3.1,1.56), (3.62,0.12,3.9,1.56), (3.62,0.12,3.9,1.56), (4.42,0.12,4.7,1.585), (4.42,0.12,4.7,1.585), (5.22,0.12,5.5,1.65), (5.22,0.12,5.5,1.65), (6.02,0.12,6.3,1.65), (6.02,0.12,6.3,1.65), (6.82,0.12,7.1,1.65), (6.82,0.12,7.1,1.65), (1.265,1.56,1.79,2.01), (1.265,1.56,1.79,2.01), (2.39,1.56,3.1,2.01), (2.39,1.56,3.1,2.01), (3.495,1.56,4.02,2.01), (3.495,1.56,4.02,2.01), (4.295,1.585,4.7,1.65), (4.295,1.585,4.7,1.65), (0.35,1.59,0.86,1.97), (0.35,1.59,0.86,1.97), (4.295,1.65,7.1,1.88), (4.295,1.65,7.1,1.88), (4.295,1.88,4.7,1.945), (4.295,1.88,4.7,1.945), (5.22,1.88,5.5,3.8), (5.22,1.88,5.5,3.8), (6.02,1.88,6.3,3.8), (6.02,1.88,6.3,3.8), (6.82,1.88,7.1,3.8), (6.82,1.88,7.1,3.8), (4.42,1.945,4.7,3.8), (4.42,1.945,4.7,3.8), (0.58,1.97,0.86,3.8), (0.58,1.97,0.86,3.8), (1.38,2.01,1.66,3.8), (1.38,2.01,1.66,3.8), (2.82,2.01,3.1,3.8), (2.82,2.01,3.1,3.8), (3.62,2.01,3.9,3.8), (3.62,2.01,3.9,3.8)])
R(gf180mcu_as_sc_mcu7t3v3_, pplus, [(-0.08,1.77,7.92,4.15), (-0.08,1.77,7.92,4.15), (0.35,1.97,1.89,2.04), (0.35,1.97,1.89,2.04), (2.59,1.97,7.33,2.04), (2.59,1.97,7.33,2.04), (-0.02,2.04,7.7,3.74), (-0.02,2.04,7.7,3.74), (0.35,3.74,1.89,3.81), (0.35,3.74,1.89,3.81), (2.59,3.74,7.33,3.81), (2.59,3.74,7.33,3.81)])
R(gf180mcu_as_sc_mcu7t3v3_, nplus, [(-0.08,-0.23,7.92,1.77), (-0.08,-0.23,7.92,1.77), (-0.08,-0.23,7.92,1.77), (-0.08,-0.23,7.92,1.77)])
R(gf180mcu_as_sc_mcu7t3v3_, contact, [(0.21,0.41,0.43,0.63), (0.21,0.41,0.43,0.63), (4.05,0.41,4.27,0.63), (4.05,0.41,4.27,0.63), (5.65,0.495,5.87,0.715), (5.65,0.495,5.87,0.715), (7.25,0.495,7.47,0.715), (7.25,0.495,7.47,0.715), (1.81,0.535,2.03,0.755), (1.81,0.535,2.03,0.755), (2.45,0.535,2.67,0.755), (2.45,0.535,2.67,0.755), (5.65,0.965,5.87,1.185), (5.65,0.965,5.87,1.185), (7.25,0.965,7.47,1.185), (7.25,0.965,7.47,1.185), (6.45,1.045,6.67,1.265), (6.45,1.045,6.67,1.265), (4.85,1.05,5.07,1.27), (4.85,1.05,5.07,1.27), (2.465,1.63,2.685,1.85), (2.465,1.63,2.685,1.85), (1.415,1.655,1.635,1.875), (1.415,1.655,1.635,1.875), (4.365,1.655,4.585,1.875), (4.365,1.655,4.585,1.875), (3.65,1.665,3.87,1.885), (3.65,1.665,3.87,1.885), (0.495,1.67,0.715,1.89), (0.495,1.67,0.715,1.89), (5.65,2.31,5.87,2.53), (5.65,2.31,5.87,2.53), (7.25,2.31,7.47,2.53), (7.25,2.31,7.47,2.53), (4.85,2.455,5.07,2.675), (4.85,2.455,5.07,2.675), (6.45,2.455,6.67,2.675), (6.45,2.455,6.67,2.675), (0.21,2.47,0.43,2.69), (0.21,2.47,0.43,2.69), (1.01,2.705,1.23,2.925), (1.01,2.705,1.23,2.925), (5.65,2.78,5.87,3), (5.65,2.78,5.87,3), (7.25,2.78,7.47,3), (7.25,2.78,7.47,3), (3.25,2.83,3.47,3.05), (3.25,2.83,3.47,3.05), (4.85,2.925,5.07,3.145), (4.85,2.925,5.07,3.145), (6.45,2.925,6.67,3.145), (6.45,2.925,6.67,3.145), (0.21,2.94,0.43,3.16), (0.21,2.94,0.43,3.16), (1.81,3.165,2.03,3.385), (1.81,3.165,2.03,3.385), (5.65,3.25,5.87,3.47), (5.65,3.25,5.87,3.47), (7.25,3.25,7.47,3.47), (7.25,3.25,7.47,3.47), (2.45,3.29,2.67,3.51), (2.45,3.29,2.67,3.51), (4.05,3.29,4.27,3.51), (4.05,3.29,4.27,3.51)])
R(gf180mcu_as_sc_mcu7t3v3_, metal1, [(0,-0.3,7.84,0.3), (0,-0.3,7.84,0.3), (0.205,0.3,0.435,0.69), (0.205,0.3,0.435,0.69), (4.045,0.3,4.275,0.69), (4.045,0.3,4.275,0.69), (5.645,0.3,5.875,1.385), (5.645,0.3,5.875,1.385), (7.245,0.3,7.475,1.385), (7.245,0.3,7.475,1.385), (1.635,0.53,3.48,0.76), (1.635,0.53,3.48,0.76), (3.25,0.76,3.48,1.015), (3.25,0.76,3.48,1.015), (4.845,0.98,5.18,1.65), (4.845,0.98,5.18,1.65), (6.445,0.98,6.78,1.65), (6.445,0.98,6.78,1.65), (3.25,1.015,4.59,1.245), (3.25,1.015,4.59,1.245), (4.36,1.245,4.59,2.24), (4.36,1.245,4.59,2.24), (0.335,1.56,0.86,2.01), (0.335,1.56,0.86,2.01), (1.265,1.56,1.79,2.01), (1.265,1.56,1.79,2.01), (2.39,1.56,2.915,2.01), (2.39,1.56,2.915,2.01), (3.495,1.56,4.02,2.01), (3.495,1.56,4.02,2.01), (4.845,1.65,6.78,1.88), (4.845,1.65,6.78,1.88), (4.845,1.88,5.18,3.39), (4.845,1.88,5.18,3.39), (6.445,1.88,6.78,3.39), (6.445,1.88,6.78,3.39), (5.645,2.155,5.875,3.62), (5.645,2.155,5.875,3.62), (7.245,2.155,7.475,3.62), (7.245,2.155,7.475,3.62), (0.205,2.24,4.59,2.47), (0.205,2.24,4.59,2.47), (0.205,2.47,0.435,3.16), (0.205,2.47,0.435,3.16), (0.9,2.7,3.475,2.93), (0.9,2.7,3.475,2.93), (3.245,2.93,3.475,3.16), (3.245,2.93,3.475,3.16), (0.205,3.16,2.09,3.39), (0.205,3.16,2.09,3.39), (2.445,3.23,2.675,3.62), (2.445,3.23,2.675,3.62), (4.045,3.23,4.275,3.62), (4.045,3.23,4.275,3.62), (0,3.62,7.84,4.22), (0,3.62,7.84,4.22)])
R(gf180mcu_as_sc_mcu7t3v3_, metal1_pin, [(0,-0.3,7.84,0.3), (0,-0.3,7.84,0.3), (4.845,0.98,5.18,3.39), (4.845,0.98,5.18,3.39), (0.335,1.56,0.86,2.01), (0.335,1.56,0.86,2.01), (1.265,1.56,1.79,2.01), (1.265,1.56,1.79,2.01), (2.39,1.56,2.915,2.01), (2.39,1.56,2.915,2.01), (3.495,1.56,4.02,2.01), (3.495,1.56,4.02,2.01), (0,3.62,7.84,4.22), (0,3.62,7.84,4.22)])
R(gf180mcu_as_sc_mcu7t3v3_, lvpwell, [(-0.43,-0.43,8.27,1.77), (-0.43,-0.43,8.27,1.77)])
R(gf180mcu_as_sc_mcu7t3v3_, lvpwell_10, [(0.05,-0.25,0.55,0.25), (0.05,-0.25,0.55,0.25)])
gf180mcu_as_sc_mcu7t3v3_.add(gdstk.Label('VDD', (3.92,3.92), layer=34, texttype=10))
gf180mcu_as_sc_mcu7t3v3_.add(gdstk.Label('VSS', (3.92,0), layer=34, texttype=10))
gf180mcu_as_sc_mcu7t3v3_.add(gdstk.Label('A', (0.597,1.785), layer=34, texttype=10))
gf180mcu_as_sc_mcu7t3v3_.add(gdstk.Label('B', (1.527,1.785), layer=34, texttype=10))
gf180mcu_as_sc_mcu7t3v3_.add(gdstk.Label('C', (2.652,1.785), layer=34, texttype=10))
gf180mcu_as_sc_mcu7t3v3_.add(gdstk.Label('D', (3.757,1.785), layer=34, texttype=10))
gf180mcu_as_sc_mcu7t3v3_.add(gdstk.Label('Y', (5.012,2.185), layer=34, texttype=10))
gf180mcu_as_sc_mcu7t3v3_.add(gdstk.Label('VDD', (3.92,3.92), layer=34, texttype=10))
gf180mcu_as_sc_mcu7t3v3_.add(gdstk.Label('VSS', (3.92,0), layer=34, texttype=10))
gf180mcu_as_sc_mcu7t3v3_.add(gdstk.Label('A', (0.597,1.785), layer=34, texttype=10))
gf180mcu_as_sc_mcu7t3v3_.add(gdstk.Label('B', (1.527,1.785), layer=34, texttype=10))
gf180mcu_as_sc_mcu7t3v3_.add(gdstk.Label('C', (2.652,1.785), layer=34, texttype=10))
gf180mcu_as_sc_mcu7t3v3_.add(gdstk.Label('D', (3.757,1.785), layer=34, texttype=10))
gf180mcu_as_sc_mcu7t3v3_.add(gdstk.Label('Y', (5.012,2.185), layer=34, texttype=10))
gf180mcu_as_sc_mcu7t3v3_.add(gdstk.Label('VNW', (0.3,3.92), layer=21, texttype=10))
gf180mcu_as_sc_mcu7t3v3_.add(gdstk.Label('VNW', (0.3,3.92), layer=21, texttype=10))
gf180mcu_as_sc_mcu7t3v3_.add(gdstk.Label('VPW', (0.3,0), layer=204, texttype=10))
gf180mcu_as_sc_mcu7t3v3_.add(gdstk.Label('VPW', (0.3,0), layer=204, texttype=10))

lib.write_gds('gf180mcu_as_sc_mcu7t3v3__ao22_4.gds')
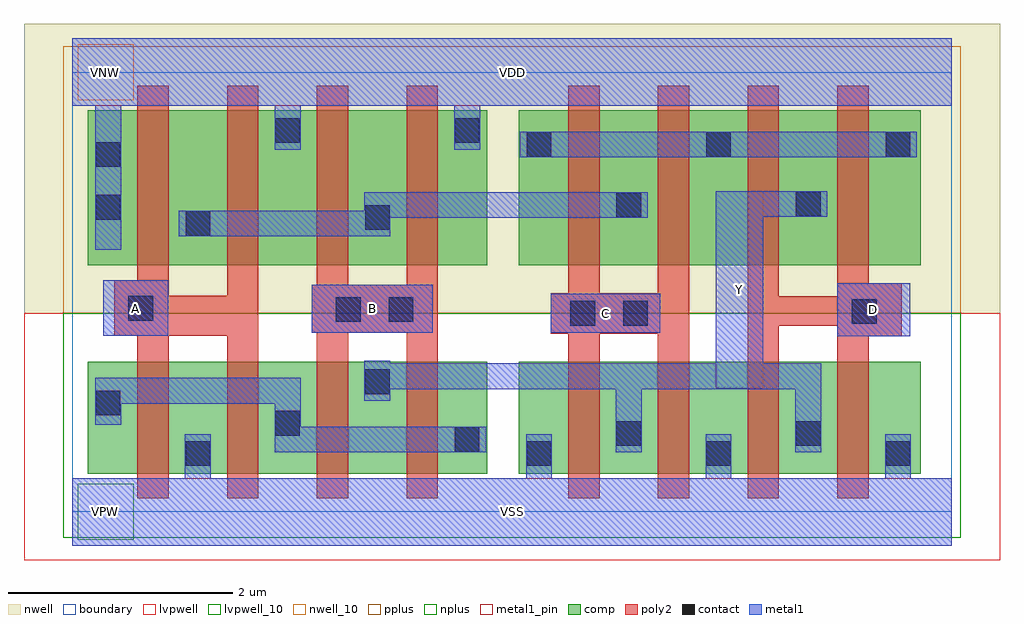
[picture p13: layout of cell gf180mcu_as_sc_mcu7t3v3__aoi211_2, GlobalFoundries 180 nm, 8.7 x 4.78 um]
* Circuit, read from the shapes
.subckt gf180mcu_as_sc_mcu7t3v3__aoi211_2 A B C D VDD VNW VSS Y
XM1 VSS A n1 VSUBS nfet_03v3 w=1u l=0.28u m=2
XM2 Y B n1 VSUBS nfet_03v3 w=1u l=0.28u m=2
XM3 Y C VSS VSUBS nfet_03v3 w=1u l=0.28u m=2
XM4 Y D VSS VSUBS nfet_03v3 w=1u l=0.28u m=2
XM5 n2 A VDD VNW pfet_03v3 w=1.38u l=0.28u m=2
XM6 n2 B VDD VNW pfet_03v3 w=1.38u l=0.28u m=2
XM7 n2 C n3 VNW pfet_03v3 w=1.38u l=0.28u m=2
XM8 Y D n3 VNW pfet_03v3 w=1.38u l=0.28u m=2
.ends

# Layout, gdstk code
import gdstk
lib = gdstk.Library(unit=1e-6, precision=1e-09)
def R(c, l, rs):  # rectangles x0, y0, x1, y1
    for r in rs: c.add(gdstk.rectangle(r[:2], r[2:], *l))
boundary = (0, 0)
nwell = (21, 0)
nwell_10 = (21, 10)
comp = (22, 0)
poly2 = (30, 0)
pplus = (31, 0)
nplus = (32, 0)
contact = (33, 0)
metal1 = (34, 0)
metal1_pin = (34, 10)
lvpwell = (204, 0)
lvpwell_10 = (204, 10)

gf180mcu_as_sc_mcu7t3v3_ = lib.new_cell('gf180mcu_as_sc_mcu7t3v3__aoi211_2')
R(gf180mcu_as_sc_mcu7t3v3_, boundary, [(0,0,7.84,3.92), (0,0,7.84,3.92)])
R(gf180mcu_as_sc_mcu7t3v3_, nwell, [(-0.43,1.77,8.27,4.35), (-0.43,1.77,8.27,4.35)])
R(gf180mcu_as_sc_mcu7t3v3_, nwell_10, [(0.05,3.67,0.55,4.17), (0.05,3.67,0.55,4.17)])
R(gf180mcu_as_sc_mcu7t3v3_, comp, [(0.14,0.34,3.7,1.34), (0.14,0.34,3.7,1.34), (3.98,0.34,7.565,1.34), (3.98,0.34,7.565,1.34), (0.14,2.2,3.7,3.58), (0.14,2.2,3.7,3.58), (3.98,2.2,7.565,3.58), (3.98,2.2,7.565,3.58)])
R(gf180mcu_as_sc_mcu7t3v3_, poly2, [(0.58,0.12,0.86,1.57), (0.58,0.12,0.86,1.57), (1.38,0.12,1.66,1.57), (1.38,0.12,1.66,1.57), (2.18,0.12,2.46,1.595), (2.18,0.12,2.46,1.595), (2.98,0.12,3.26,1.595), (2.98,0.12,3.26,1.595), (4.42,0.12,4.7,1.59), (4.42,0.12,4.7,1.59), (5.22,0.12,5.5,1.59), (5.22,0.12,5.5,1.59), (6.02,0.12,6.3,1.66), (6.02,0.12,6.3,1.66), (6.82,0.12,7.1,1.565), (6.82,0.12,7.1,1.565), (6.82,1.565,7.395,1.66), (6.82,1.565,7.395,1.66), (0.375,1.57,1.66,1.925), (0.375,1.57,1.66,1.925), (4.265,1.59,5.5,1.95), (4.265,1.59,5.5,1.95), (2.135,1.595,3.26,2.025), (2.135,1.595,3.26,2.025), (6.02,1.66,7.395,1.92), (6.02,1.66,7.395,1.92), (6.02,1.92,6.3,3.8), (6.02,1.92,6.3,3.8), (6.82,1.92,7.395,2.04), (6.82,1.92,7.395,2.04), (0.375,1.925,0.86,2.065), (0.375,1.925,0.86,2.065), (1.38,1.925,1.66,3.8), (1.38,1.925,1.66,3.8), (4.42,1.95,4.7,3.8), (4.42,1.95,4.7,3.8), (5.22,1.95,5.5,3.8), (5.22,1.95,5.5,3.8), (2.18,2.025,2.46,3.8), (2.18,2.025,2.46,3.8), (2.98,2.025,3.26,3.8), (2.98,2.025,3.26,3.8), (6.82,2.04,7.1,3.8), (6.82,2.04,7.1,3.8), (0.58,2.065,0.86,3.8), (0.58,2.065,0.86,3.8)])
R(gf180mcu_as_sc_mcu7t3v3_, pplus, [(-0.08,1.77,7.92,4.15), (-0.08,1.77,7.92,4.15), (0.35,1.97,3.49,2.04), (0.35,1.97,3.49,2.04), (4.19,1.97,7.33,2.04), (4.19,1.97,7.33,2.04), (-0.02,2.04,7.725,3.74), (-0.02,2.04,7.725,3.74), (0.35,3.74,3.49,3.81), (0.35,3.74,3.49,3.81), (4.19,3.74,7.33,3.81), (4.19,3.74,7.33,3.81)])
R(gf180mcu_as_sc_mcu7t3v3_, nplus, [(-0.08,-0.23,7.92,1.77), (-0.08,-0.23,7.92,1.77), (-0.08,-0.23,7.92,1.77), (-0.08,-0.23,7.92,1.77)])
R(gf180mcu_as_sc_mcu7t3v3_, contact, [(1.01,0.41,1.23,0.63), (1.01,0.41,1.23,0.63), (4.05,0.41,4.27,0.63), (4.05,0.41,4.27,0.63), (5.65,0.41,5.87,0.63), (5.65,0.41,5.87,0.63), (7.25,0.41,7.47,0.63), (7.25,0.41,7.47,0.63), (3.41,0.535,3.63,0.755), (3.41,0.535,3.63,0.755), (4.85,0.59,5.07,0.81), (4.85,0.59,5.07,0.81), (6.45,0.59,6.67,0.81), (6.45,0.59,6.67,0.81), (1.81,0.68,2.03,0.9), (1.81,0.68,2.03,0.9), (0.21,0.86,0.43,1.08), (0.21,0.86,0.43,1.08), (2.61,1.05,2.83,1.27), (2.61,1.05,2.83,1.27), (4.44,1.66,4.66,1.88), (4.44,1.66,4.66,1.88), (4.91,1.66,5.13,1.88), (4.91,1.66,5.13,1.88), (6.95,1.675,7.17,1.895), (6.95,1.675,7.17,1.895), (2.35,1.695,2.57,1.915), (2.35,1.695,2.57,1.915), (2.82,1.695,3.04,1.915), (2.82,1.695,3.04,1.915), (0.5,1.705,0.72,1.925), (0.5,1.705,0.72,1.925), (1.01,2.46,1.23,2.68), (1.01,2.46,1.23,2.68), (2.61,2.515,2.83,2.735), (2.61,2.515,2.83,2.735), (0.21,2.605,0.43,2.825), (0.21,2.605,0.43,2.825), (4.85,2.625,5.07,2.845), (4.85,2.625,5.07,2.845), (6.45,2.635,6.67,2.855), (6.45,2.635,6.67,2.855), (0.21,3.075,0.43,3.295), (0.21,3.075,0.43,3.295), (4.05,3.165,4.27,3.385), (4.05,3.165,4.27,3.385), (5.65,3.165,5.87,3.385), (5.65,3.165,5.87,3.385), (7.25,3.165,7.47,3.385), (7.25,3.165,7.47,3.385), (1.81,3.29,2.03,3.51), (1.81,3.29,2.03,3.51), (3.41,3.29,3.63,3.51), (3.41,3.29,3.63,3.51)])
R(gf180mcu_as_sc_mcu7t3v3_, metal1, [(0,-0.3,7.84,0.3), (0,-0.3,7.84,0.3), (1.005,0.3,1.235,0.69), (1.005,0.3,1.235,0.69), (4.045,0.3,4.275,0.69), (4.045,0.3,4.275,0.69), (5.645,0.3,5.875,0.69), (5.645,0.3,5.875,0.69), (7.245,0.3,7.475,0.69), (7.245,0.3,7.475,0.69), (1.805,0.53,3.69,0.76), (1.805,0.53,3.69,0.76), (4.845,0.53,5.075,1.095), (4.845,0.53,5.075,1.095), (6.445,0.53,6.675,1.095), (6.445,0.53,6.675,1.095), (1.805,0.76,2.035,0.965), (1.805,0.76,2.035,0.965), (0.205,0.775,0.435,0.965), (0.205,0.775,0.435,0.965), (0.205,0.965,2.035,1.195), (0.205,0.965,2.035,1.195), (2.605,0.99,2.835,1.095), (2.605,0.99,2.835,1.095), (2.605,1.095,6.675,1.325), (2.605,1.095,6.675,1.325), (2.605,1.325,2.835,1.345), (2.605,1.325,2.835,1.345), (5.735,1.325,6.16,2.63), (5.735,1.325,6.16,2.63), (6.82,1.565,7.47,2.04), (6.82,1.565,7.47,2.04), (0.275,1.57,0.855,2.065), (0.275,1.57,0.855,2.065), (2.135,1.595,3.215,2.025), (2.135,1.595,3.215,2.025), (4.265,1.595,5.24,1.945), (4.265,1.595,5.24,1.945), (0.205,2.335,0.435,3.62), (0.205,2.335,0.435,3.62), (0.95,2.455,2.835,2.62), (0.95,2.455,2.835,2.62), (0.95,2.62,5.13,2.685), (0.95,2.62,5.13,2.685), (5.735,2.63,6.73,2.86), (5.735,2.63,6.73,2.86), (2.605,2.685,5.13,2.85), (2.605,2.685,5.13,2.85), (3.99,3.16,7.53,3.39), (3.99,3.16,7.53,3.39), (1.805,3.23,2.035,3.62), (1.805,3.23,2.035,3.62), (3.405,3.23,3.635,3.62), (3.405,3.23,3.635,3.62), (0,3.62,7.84,4.22), (0,3.62,7.84,4.22)])
R(gf180mcu_as_sc_mcu7t3v3_, metal1_pin, [(0,-0.3,7.84,0.3), (0,-0.3,7.84,0.3), (5.735,1.1,6.16,2.86), (5.735,1.1,6.16,2.86), (6.82,1.565,7.47,2.04), (6.82,1.565,7.47,2.04), (0.275,1.57,0.855,2.065), (0.275,1.57,0.855,2.065), (2.135,1.595,3.215,2.025), (2.135,1.595,3.215,2.025), (4.265,1.595,5.24,1.945), (4.265,1.595,5.24,1.945), (0,3.62,7.84,4.22), (0,3.62,7.84,4.22)])
R(gf180mcu_as_sc_mcu7t3v3_, lvpwell, [(-0.43,-0.43,8.27,1.77), (-0.43,-0.43,8.27,1.77)])
R(gf180mcu_as_sc_mcu7t3v3_, lvpwell_10, [(0.05,-0.25,0.55,0.25), (0.05,-0.25,0.55,0.25)])
gf180mcu_as_sc_mcu7t3v3_.add(gdstk.Label('VDD', (3.92,3.92), layer=34, texttype=10))
gf180mcu_as_sc_mcu7t3v3_.add(gdstk.Label('VSS', (3.92,0), layer=34, texttype=10))
gf180mcu_as_sc_mcu7t3v3_.add(gdstk.Label('A', (0.565,1.817), layer=34, texttype=10))
gf180mcu_as_sc_mcu7t3v3_.add(gdstk.Label('B', (2.675,1.81), layer=34, texttype=10))
gf180mcu_as_sc_mcu7t3v3_.add(gdstk.Label('C', (4.752,1.77), layer=34, texttype=10))
gf180mcu_as_sc_mcu7t3v3_.add(gdstk.Label('Y', (5.947,1.98), layer=34, texttype=10))
gf180mcu_as_sc_mcu7t3v3_.add(gdstk.Label('D', (7.145,1.802), layer=34, texttype=10))
gf180mcu_as_sc_mcu7t3v3_.add(gdstk.Label('VDD', (3.92,3.92), layer=34, texttype=10))
gf180mcu_as_sc_mcu7t3v3_.add(gdstk.Label('VSS', (3.92,0), layer=34, texttype=10))
gf180mcu_as_sc_mcu7t3v3_.add(gdstk.Label('A', (0.565,1.817), layer=34, texttype=10))
gf180mcu_as_sc_mcu7t3v3_.add(gdstk.Label('B', (2.675,1.81), layer=34, texttype=10))
gf180mcu_as_sc_mcu7t3v3_.add(gdstk.Label('C', (4.752,1.77), layer=34, texttype=10))
gf180mcu_as_sc_mcu7t3v3_.add(gdstk.Label('Y', (5.947,1.98), layer=34, texttype=10))
gf180mcu_as_sc_mcu7t3v3_.add(gdstk.Label('D', (7.145,1.802), layer=34, texttype=10))
gf180mcu_as_sc_mcu7t3v3_.add(gdstk.Label('VNW', (0.3,3.92), layer=21, texttype=10))
gf180mcu_as_sc_mcu7t3v3_.add(gdstk.Label('VNW', (0.3,3.92), layer=21, texttype=10))
gf180mcu_as_sc_mcu7t3v3_.add(gdstk.Label('VPW', (0.3,0), layer=204, texttype=10))
gf180mcu_as_sc_mcu7t3v3_.add(gdstk.Label('VPW', (0.3,0), layer=204, texttype=10))

lib.write_gds('gf180mcu_as_sc_mcu7t3v3__aoi211_2.gds')
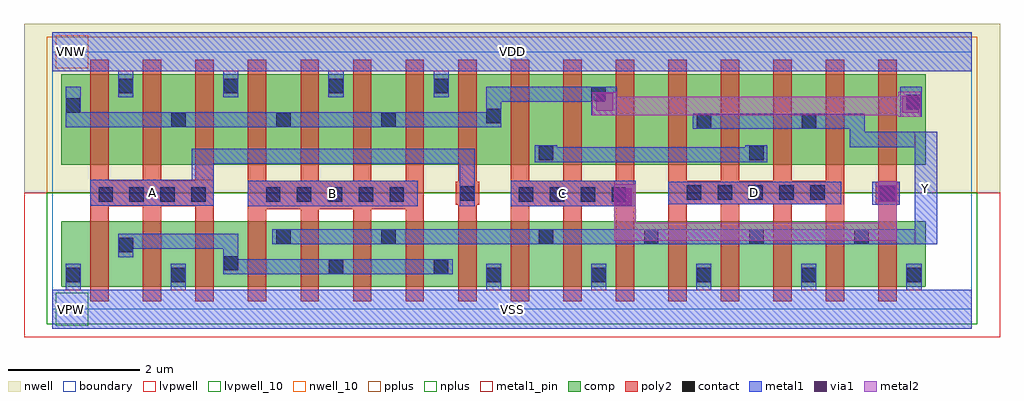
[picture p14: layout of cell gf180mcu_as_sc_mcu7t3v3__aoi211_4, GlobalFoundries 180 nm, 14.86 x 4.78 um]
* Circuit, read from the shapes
.subckt gf180mcu_as_sc_mcu7t3v3__aoi211_4 A B C D VDD VNW VSS Y
XM1 n1 A VSS VSUBS nfet_03v3 w=1u l=0.28u m=4
XM2 Y B n1 VSUBS nfet_03v3 w=1u l=0.28u m=4
XM3 Y C VSS VSUBS nfet_03v3 w=1u l=0.28u m=4
XM4 VSS D Y VSUBS nfet_03v3 w=1u l=0.28u m=4
XM5 VDD A n2 VNW pfet_03v3 w=1.38u l=0.28u m=4
XM6 n2 B VDD VNW pfet_03v3 w=1.38u l=0.28u m=4
XM7 n3 C n2 VNW pfet_03v3 w=1.38u l=0.28u m=2
XM8 n4 C n2 VNW pfet_03v3 w=1.38u l=0.28u
XM9 Y D n4 VNW pfet_03v3 w=1.38u l=0.28u
XM10 n3 D Y VNW pfet_03v3 w=1.38u l=0.28u m=2
XM11 n5 D Y VNW pfet_03v3 w=1.38u l=0.28u
XM12 n2 C n5 VNW pfet_03v3 w=1.38u l=0.28u
.ends

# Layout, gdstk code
import gdstk
lib = gdstk.Library(unit=1e-6, precision=1e-09)
def R(c, l, rs):  # rectangles x0, y0, x1, y1
    for r in rs: c.add(gdstk.rectangle(r[:2], r[2:], *l))
boundary = (0, 0)
nwell = (21, 0)
nwell_10 = (21, 10)
comp = (22, 0)
poly2 = (30, 0)
pplus = (31, 0)
nplus = (32, 0)
contact = (33, 0)
metal1 = (34, 0)
metal1_pin = (34, 10)
via1 = (35, 0)
metal2 = (36, 0)
lvpwell = (204, 0)
lvpwell_10 = (204, 10)

gf180mcu_as_sc_mcu7t3v3_ = lib.new_cell('gf180mcu_as_sc_mcu7t3v3__aoi211_4')
R(gf180mcu_as_sc_mcu7t3v3_, boundary, [(0,0,14,3.92), (0,0,14,3.92)])
R(gf180mcu_as_sc_mcu7t3v3_, nwell, [(-0.43,1.77,14.43,4.35), (-0.43,1.77,14.43,4.35)])
R(gf180mcu_as_sc_mcu7t3v3_, nwell_10, [(0.05,3.67,0.55,4.17), (0.05,3.67,0.55,4.17)])
R(gf180mcu_as_sc_mcu7t3v3_, comp, [(0.14,0.34,13.3,1.34), (0.14,0.34,13.3,1.34), (0.14,2.2,13.3,3.58), (0.14,2.2,13.3,3.58)])
R(gf180mcu_as_sc_mcu7t3v3_, poly2, [(0.58,0.12,0.86,1.57), (0.58,0.12,0.86,1.57), (1.38,0.12,1.66,1.57), (1.38,0.12,1.66,1.57), (2.18,0.12,2.46,1.57), (2.18,0.12,2.46,1.57), (2.98,0.12,3.26,1.52), (2.98,0.12,3.26,1.52), (3.78,0.12,4.06,1.52), (3.78,0.12,4.06,1.52), (4.58,0.12,4.86,1.52), (4.58,0.12,4.86,1.52), (5.38,0.12,5.66,1.52), (5.38,0.12,5.66,1.52), (6.18,0.12,6.46,1.59), (6.18,0.12,6.46,1.59), (6.98,0.12,7.26,1.565), (6.98,0.12,7.26,1.565), (7.78,0.12,8.06,1.565), (7.78,0.12,8.06,1.565), (8.58,0.12,8.86,1.565), (8.58,0.12,8.86,1.565), (9.38,0.12,9.66,1.6), (9.38,0.12,9.66,1.6), (10.18,0.12,10.46,1.6), (10.18,0.12,10.46,1.6), (10.98,0.12,11.26,1.6), (10.98,0.12,11.26,1.6), (11.78,0.12,12.06,1.6), (11.78,0.12,12.06,1.6), (12.58,0.12,12.86,1.59), (12.58,0.12,12.86,1.59), (2.98,1.52,5.66,1.96), (2.98,1.52,5.66,1.96), (6.98,1.565,8.86,1.955), (6.98,1.565,8.86,1.955), (0.58,1.57,2.46,1.965), (0.58,1.57,2.46,1.965), (6.14,1.59,6.5,1.94), (6.14,1.59,6.5,1.94), (12.54,1.59,12.9,1.94), (12.54,1.59,12.9,1.94), (9.38,1.6,12.06,1.96), (9.38,1.6,12.06,1.96), (6.18,1.94,6.46,3.8), (6.18,1.94,6.46,3.8), (12.58,1.94,12.86,3.8), (12.58,1.94,12.86,3.8), (6.98,1.955,7.26,3.8), (6.98,1.955,7.26,3.8), (7.78,1.955,8.06,3.8), (7.78,1.955,8.06,3.8), (8.58,1.955,8.86,3.8), (8.58,1.955,8.86,3.8), (2.98,1.96,3.26,3.8), (2.98,1.96,3.26,3.8), (3.78,1.96,4.06,3.8), (3.78,1.96,4.06,3.8), (4.58,1.96,4.86,3.8), (4.58,1.96,4.86,3.8), (5.38,1.96,5.66,3.8), (5.38,1.96,5.66,3.8), (9.38,1.96,9.66,3.8), (9.38,1.96,9.66,3.8), (10.18,1.96,10.46,3.8), (10.18,1.96,10.46,3.8), (10.98,1.96,11.26,3.8), (10.98,1.96,11.26,3.8), (11.78,1.96,12.06,3.8), (11.78,1.96,12.06,3.8), (0.58,1.965,0.86,3.8), (0.58,1.965,0.86,3.8), (1.38,1.965,1.66,3.8), (1.38,1.965,1.66,3.8), (2.18,1.965,2.46,3.8), (2.18,1.965,2.46,3.8)])
R(gf180mcu_as_sc_mcu7t3v3_, pplus, [(-0.08,1.77,14.08,4.15), (-0.08,1.77,14.08,4.15), (0.35,1.97,13.09,2.04), (0.35,1.97,13.09,2.04), (-0.02,2.04,13.46,3.74), (-0.02,2.04,13.46,3.74), (0.35,3.74,13.09,3.81), (0.35,3.74,13.09,3.81)])
R(gf180mcu_as_sc_mcu7t3v3_, nplus, [(-0.08,-0.23,14.08,1.77), (-0.08,-0.23,14.08,1.77), (-0.08,-0.23,14.08,1.77), (-0.08,-0.23,14.08,1.77)])
R(gf180mcu_as_sc_mcu7t3v3_, contact, [(0.21,0.41,0.43,0.63), (0.21,0.41,0.43,0.63), (1.81,0.41,2.03,0.63), (1.81,0.41,2.03,0.63), (6.61,0.41,6.83,0.63), (6.61,0.41,6.83,0.63), (8.21,0.41,8.43,0.63), (8.21,0.41,8.43,0.63), (9.81,0.41,10.03,0.63), (9.81,0.41,10.03,0.63), (11.41,0.41,11.63,0.63), (11.41,0.41,11.63,0.63), (13.01,0.41,13.23,0.63), (13.01,0.41,13.23,0.63), (4.21,0.535,4.43,0.755), (4.21,0.535,4.43,0.755), (5.81,0.535,6.03,0.755), (5.81,0.535,6.03,0.755), (2.61,0.59,2.83,0.81), (2.61,0.59,2.83,0.81), (1.01,0.865,1.23,1.085), (1.01,0.865,1.23,1.085), (3.41,0.995,3.63,1.215), (3.41,0.995,3.63,1.215), (5.01,0.995,5.23,1.215), (5.01,0.995,5.23,1.215), (7.41,0.995,7.63,1.215), (7.41,0.995,7.63,1.215), (9.01,0.995,9.23,1.215), (9.01,0.995,9.23,1.215), (10.61,0.995,10.83,1.215), (10.61,0.995,10.83,1.215), (12.21,0.995,12.43,1.215), (12.21,0.995,12.43,1.215), (0.705,1.64,0.925,1.86), (0.705,1.64,0.925,1.86), (1.175,1.64,1.395,1.86), (1.175,1.64,1.395,1.86), (1.645,1.64,1.865,1.86), (1.645,1.64,1.865,1.86), (2.115,1.64,2.335,1.86), (2.115,1.64,2.335,1.86), (3.255,1.64,3.475,1.86), (3.255,1.64,3.475,1.86), (3.725,1.64,3.945,1.86), (3.725,1.64,3.945,1.86), (4.195,1.64,4.415,1.86), (4.195,1.64,4.415,1.86), (4.665,1.64,4.885,1.86), (4.665,1.64,4.885,1.86), (5.135,1.64,5.355,1.86), (5.135,1.64,5.355,1.86), (7.105,1.64,7.325,1.86), (7.105,1.64,7.325,1.86), (7.575,1.64,7.795,1.86), (7.575,1.64,7.795,1.86), (8.045,1.64,8.265,1.86), (8.045,1.64,8.265,1.86), (8.515,1.64,8.735,1.86), (8.515,1.64,8.735,1.86), (6.21,1.655,6.43,1.875), (6.21,1.655,6.43,1.875), (12.61,1.655,12.83,1.875), (12.61,1.655,12.83,1.875), (9.66,1.67,9.88,1.89), (9.66,1.67,9.88,1.89), (10.13,1.67,10.35,1.89), (10.13,1.67,10.35,1.89), (10.6,1.67,10.82,1.89), (10.6,1.67,10.82,1.89), (11.07,1.67,11.29,1.89), (11.07,1.67,11.29,1.89), (11.54,1.67,11.76,1.89), (11.54,1.67,11.76,1.89), (7.41,2.27,7.63,2.49), (7.41,2.27,7.63,2.49), (10.61,2.27,10.83,2.49), (10.61,2.27,10.83,2.49), (9.81,2.75,10.03,2.97), (9.81,2.75,10.03,2.97), (11.41,2.75,11.63,2.97), (11.41,2.75,11.63,2.97), (1.81,2.775,2.03,2.995), (1.81,2.775,2.03,2.995), (3.41,2.775,3.63,2.995), (3.41,2.775,3.63,2.995), (5.01,2.775,5.23,2.995), (5.01,2.775,5.23,2.995), (6.61,2.83,6.83,3.05), (6.61,2.83,6.83,3.05), (0.21,2.995,0.43,3.215), (0.21,2.995,0.43,3.215), (13.01,3.045,13.23,3.265), (13.01,3.045,13.23,3.265), (8.21,3.165,8.43,3.385), (8.21,3.165,8.43,3.385), (1.01,3.29,1.23,3.51), (1.01,3.29,1.23,3.51), (2.61,3.29,2.83,3.51), (2.61,3.29,2.83,3.51), (4.21,3.29,4.43,3.51), (4.21,3.29,4.43,3.51), (5.81,3.29,6.03,3.51), (5.81,3.29,6.03,3.51)])
R(gf180mcu_as_sc_mcu7t3v3_, metal1, [(0,-0.3,14,0.3), (0,-0.3,14,0.3), (0.205,0.3,0.435,0.69), (0.205,0.3,0.435,0.69), (1.805,0.3,2.035,0.69), (1.805,0.3,2.035,0.69), (6.605,0.3,6.835,0.69), (6.605,0.3,6.835,0.69), (8.205,0.3,8.435,0.69), (8.205,0.3,8.435,0.69), (9.805,0.3,10.035,0.69), (9.805,0.3,10.035,0.69), (11.405,0.3,11.635,0.69), (11.405,0.3,11.635,0.69), (13.005,0.3,13.235,0.69), (13.005,0.3,13.235,0.69), (2.605,0.53,6.095,0.76), (2.605,0.53,6.095,0.76), (2.605,0.76,2.835,0.92), (2.605,0.76,2.835,0.92), (1.005,0.79,1.235,0.92), (1.005,0.79,1.235,0.92), (1.005,0.92,2.835,1.15), (1.005,0.92,2.835,1.15), (3.35,0.99,13.475,1.22), (3.35,0.99,13.475,1.22), (13.13,1.22,13.475,2.47), (13.13,1.22,13.475,2.47), (2.98,1.565,5.565,1.96), (2.98,1.565,5.565,1.96), (6.98,1.565,8.885,1.955), (6.98,1.565,8.885,1.955), (6.205,1.57,6.435,2.215), (6.205,1.57,6.435,2.215), (0.58,1.575,2.46,1.975), (0.58,1.575,2.46,1.975), (12.485,1.59,12.9,1.94), (12.485,1.59,12.9,1.94), (9.38,1.6,12.015,1.94), (9.38,1.6,12.015,1.94), (2.125,1.975,2.46,2.215), (2.125,1.975,2.46,2.215), (2.125,2.215,6.435,2.445), (2.125,2.215,6.435,2.445), (7.35,2.24,10.89,2.47), (7.35,2.24,10.89,2.47), (7.35,2.47,7.69,2.495), (7.35,2.47,7.69,2.495), (10.55,2.47,10.89,2.495), (10.55,2.47,10.89,2.495), (12.14,2.47,13.475,2.7), (12.14,2.47,13.475,2.7), (12.14,2.7,12.37,2.745), (12.14,2.7,12.37,2.745), (9.75,2.745,12.37,2.975), (9.75,2.745,12.37,2.975), (0.205,2.77,6.835,3), (0.205,2.77,6.835,3), (12.915,2.93,13.235,3.39), (12.915,2.93,13.235,3.39), (8.205,2.955,8.595,3.16), (8.205,2.955,8.595,3.16), (0.205,3,0.435,3.39), (0.205,3,0.435,3.39), (6.605,3,6.835,3.16), (6.605,3,6.835,3.16), (6.605,3.16,8.595,3.39), (6.605,3.16,8.595,3.39), (1.005,3.23,1.235,3.62), (1.005,3.23,1.235,3.62), (2.605,3.23,2.835,3.62), (2.605,3.23,2.835,3.62), (4.205,3.23,4.435,3.62), (4.205,3.23,4.435,3.62), (5.805,3.23,6.035,3.62), (5.805,3.23,6.035,3.62), (0,3.62,14,4.22), (0,3.62,14,4.22)])
R(gf180mcu_as_sc_mcu7t3v3_, metal1_pin, [(0,-0.3,14,0.3), (0,-0.3,14,0.3), (13.13,0.99,13.475,2.7), (13.13,0.99,13.475,2.7), (2.98,1.565,5.565,1.96), (2.98,1.565,5.565,1.96), (6.98,1.565,8.565,1.955), (6.98,1.565,8.565,1.955), (0.58,1.575,2.46,1.975), (0.58,1.575,2.46,1.975), (9.38,1.6,12.015,1.94), (9.38,1.6,12.015,1.94), (0,3.62,14,4.22), (0,3.62,14,4.22)])
R(gf180mcu_as_sc_mcu7t3v3_, via1, [(8.565,1.585,8.825,1.845), (8.565,1.585,8.825,1.845), (12.59,1.63,12.85,1.89), (12.59,1.63,12.85,1.89), (12.94,2.99,13.2,3.25), (12.94,2.99,13.2,3.25), (8.28,3.025,8.54,3.285), (8.28,3.025,8.54,3.285)])
R(gf180mcu_as_sc_mcu7t3v3_, metal2, [(8.555,1.04,12.86,1.32), (8.555,1.04,12.86,1.32), (8.555,1.32,8.885,1.905), (8.555,1.32,8.885,1.905), (12.58,1.32,12.86,1.95), (12.58,1.32,12.86,1.95), (12.88,2.93,13.225,2.955), (12.88,2.93,13.225,2.955), (8.22,2.955,13.225,3.235), (8.22,2.955,13.225,3.235), (8.22,3.235,8.6,3.305), (8.22,3.235,8.6,3.305), (12.88,3.235,13.225,3.31), (12.88,3.235,13.225,3.31)])
R(gf180mcu_as_sc_mcu7t3v3_, lvpwell, [(-0.43,-0.43,14.43,1.77), (-0.43,-0.43,14.43,1.77)])
R(gf180mcu_as_sc_mcu7t3v3_, lvpwell_10, [(0.05,-0.25,0.55,0.25), (0.05,-0.25,0.55,0.25)])
gf180mcu_as_sc_mcu7t3v3_.add(gdstk.Label('VDD', (7,3.92), layer=34, texttype=10))
gf180mcu_as_sc_mcu7t3v3_.add(gdstk.Label('VSS', (7,0), layer=34, texttype=10))
gf180mcu_as_sc_mcu7t3v3_.add(gdstk.Label('A', (1.52,1.775), layer=34, texttype=10))
gf180mcu_as_sc_mcu7t3v3_.add(gdstk.Label('B', (4.272,1.762), layer=34, texttype=10))
gf180mcu_as_sc_mcu7t3v3_.add(gdstk.Label('C', (7.772,1.76), layer=34, texttype=10))
gf180mcu_as_sc_mcu7t3v3_.add(gdstk.Label('D', (10.697,1.77), layer=34, texttype=10))
gf180mcu_as_sc_mcu7t3v3_.add(gdstk.Label('Y', (13.302,1.845), layer=34, texttype=10))
gf180mcu_as_sc_mcu7t3v3_.add(gdstk.Label('VDD', (7,3.92), layer=34, texttype=10))
gf180mcu_as_sc_mcu7t3v3_.add(gdstk.Label('VSS', (7,0), layer=34, texttype=10))
gf180mcu_as_sc_mcu7t3v3_.add(gdstk.Label('A', (1.52,1.775), layer=34, texttype=10))
gf180mcu_as_sc_mcu7t3v3_.add(gdstk.Label('B', (4.272,1.762), layer=34, texttype=10))
gf180mcu_as_sc_mcu7t3v3_.add(gdstk.Label('C', (7.772,1.76), layer=34, texttype=10))
gf180mcu_as_sc_mcu7t3v3_.add(gdstk.Label('D', (10.697,1.77), layer=34, texttype=10))
gf180mcu_as_sc_mcu7t3v3_.add(gdstk.Label('Y', (13.302,1.845), layer=34, texttype=10))
gf180mcu_as_sc_mcu7t3v3_.add(gdstk.Label('VNW', (0.3,3.92), layer=21, texttype=10))
gf180mcu_as_sc_mcu7t3v3_.add(gdstk.Label('VNW', (0.3,3.92), layer=21, texttype=10))
gf180mcu_as_sc_mcu7t3v3_.add(gdstk.Label('VPW', (0.3,0), layer=204, texttype=10))
gf180mcu_as_sc_mcu7t3v3_.add(gdstk.Label('VPW', (0.3,0), layer=204, texttype=10))

lib.write_gds('gf180mcu_as_sc_mcu7t3v3__aoi211_4.gds')
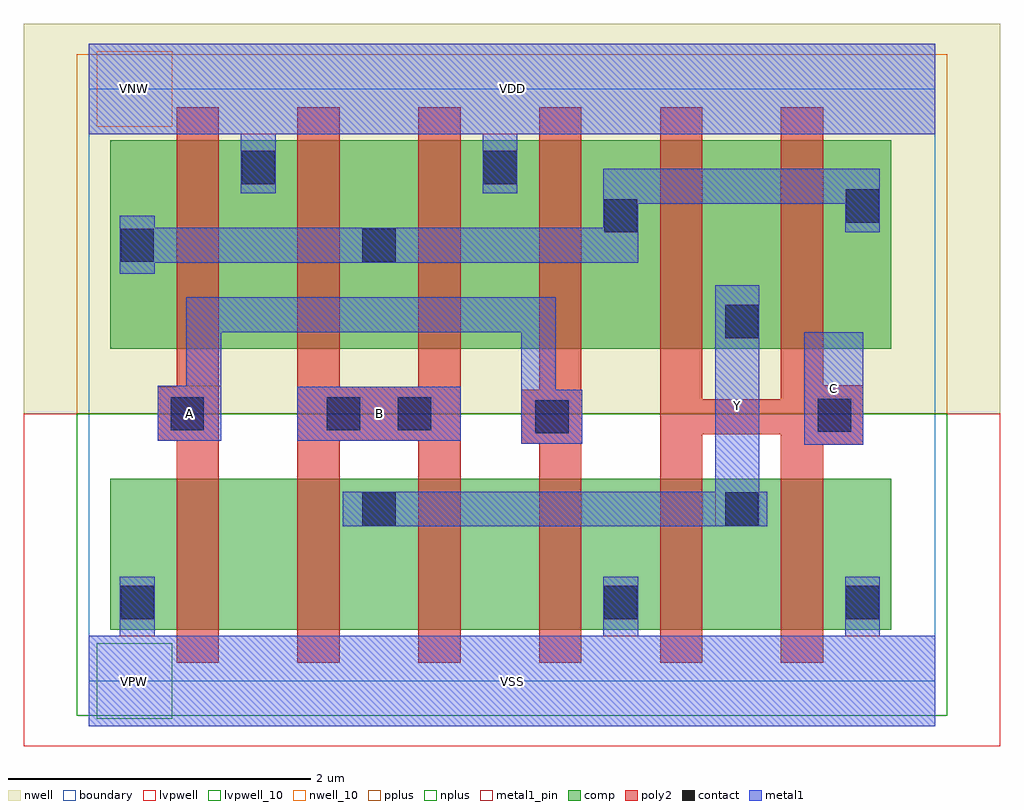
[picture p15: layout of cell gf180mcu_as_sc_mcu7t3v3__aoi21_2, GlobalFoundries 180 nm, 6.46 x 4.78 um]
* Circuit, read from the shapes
.subckt gf180mcu_as_sc_mcu7t3v3__aoi21_2 A B C VDD VNW VSS Y
XM1 n1 A VSS VSUBS nfet_03v3 w=1u l=0.28u
XM2 Y B n1 VSUBS nfet_03v3 w=1u l=0.28u
XM3 n2 B Y VSUBS nfet_03v3 w=1u l=0.28u
XM4 VSS A n2 VSUBS nfet_03v3 w=1u l=0.28u
XM5 Y C VSS VSUBS nfet_03v3 w=1u l=0.28u m=2
XM6 VDD A n3 VNW pfet_03v3 w=1.38u l=0.28u m=2
XM7 n3 B VDD VNW pfet_03v3 w=1.38u l=0.28u m=2
XM8 Y C n3 VNW pfet_03v3 w=1.38u l=0.28u m=2
.ends

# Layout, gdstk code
import gdstk
lib = gdstk.Library(unit=1e-6, precision=1e-09)
def R(c, l, rs):  # rectangles x0, y0, x1, y1
    for r in rs: c.add(gdstk.rectangle(r[:2], r[2:], *l))
boundary = (0, 0)
nwell = (21, 0)
nwell_10 = (21, 10)
comp = (22, 0)
poly2 = (30, 0)
pplus = (31, 0)
nplus = (32, 0)
contact = (33, 0)
metal1 = (34, 0)
metal1_pin = (34, 10)
lvpwell = (204, 0)
lvpwell_10 = (204, 10)

gf180mcu_as_sc_mcu7t3v3_ = lib.new_cell('gf180mcu_as_sc_mcu7t3v3__aoi21_2')
R(gf180mcu_as_sc_mcu7t3v3_, boundary, [(0,0,5.6,3.92), (0,0,5.6,3.92)])
R(gf180mcu_as_sc_mcu7t3v3_, nwell, [(-0.43,1.77,6.03,4.35), (-0.43,1.77,6.03,4.35)])
R(gf180mcu_as_sc_mcu7t3v3_, nwell_10, [(0.05,3.67,0.55,4.17), (0.05,3.67,0.55,4.17)])
R(gf180mcu_as_sc_mcu7t3v3_, comp, [(0.14,0.34,5.31,1.34), (0.14,0.34,5.31,1.34), (0.14,2.2,5.31,3.58), (0.14,2.2,5.31,3.58)])
R(gf180mcu_as_sc_mcu7t3v3_, poly2, [(0.58,0.12,0.86,1.59), (0.58,0.12,0.86,1.59), (1.38,0.12,1.66,1.59), (1.38,0.12,1.66,1.59), (2.18,0.12,2.46,1.59), (2.18,0.12,2.46,1.59), (2.98,0.12,3.26,1.57), (2.98,0.12,3.26,1.57), (3.78,0.12,4.06,1.635), (3.78,0.12,4.06,1.635), (4.58,0.12,4.86,1.565), (4.58,0.12,4.86,1.565), (4.58,1.565,5.125,1.635), (4.58,1.565,5.125,1.635), (2.86,1.57,3.265,1.93), (2.86,1.57,3.265,1.93), (0.455,1.59,0.86,1.95), (0.455,1.59,0.86,1.95), (1.38,1.59,2.46,1.95), (1.38,1.59,2.46,1.95), (3.78,1.635,5.125,1.865), (3.78,1.635,5.125,1.865), (3.78,1.865,4.06,3.8), (3.78,1.865,4.06,3.8), (4.58,1.865,5.125,1.96), (4.58,1.865,5.125,1.96), (2.98,1.93,3.26,3.8), (2.98,1.93,3.26,3.8), (0.58,1.95,0.86,3.8), (0.58,1.95,0.86,3.8), (1.38,1.95,1.66,3.8), (1.38,1.95,1.66,3.8), (2.18,1.95,2.46,3.8), (2.18,1.95,2.46,3.8), (4.58,1.96,4.86,3.8), (4.58,1.96,4.86,3.8)])
R(gf180mcu_as_sc_mcu7t3v3_, pplus, [(-0.08,1.77,5.68,4.15), (-0.08,1.77,5.68,4.15), (0.35,1.97,5.09,2.04), (0.35,1.97,5.09,2.04), (-0.02,2.04,5.47,3.74), (-0.02,2.04,5.47,3.74), (0.35,3.74,5.09,3.81), (0.35,3.74,5.09,3.81)])
R(gf180mcu_as_sc_mcu7t3v3_, nplus, [(-0.08,-0.23,5.68,1.77), (-0.08,-0.23,5.68,1.77), (-0.08,-0.23,5.68,1.77), (-0.08,-0.23,5.68,1.77)])
R(gf180mcu_as_sc_mcu7t3v3_, contact, [(0.21,0.41,0.43,0.63), (0.21,0.41,0.43,0.63), (3.41,0.41,3.63,0.63), (3.41,0.41,3.63,0.63), (5.01,0.41,5.23,0.63), (5.01,0.41,5.23,0.63), (1.81,1.03,2.03,1.25), (1.81,1.03,2.03,1.25), (4.21,1.03,4.43,1.25), (4.21,1.03,4.43,1.25), (2.955,1.64,3.175,1.86), (2.955,1.64,3.175,1.86), (4.825,1.65,5.045,1.87), (4.825,1.65,5.045,1.87), (0.54,1.66,0.76,1.88), (0.54,1.66,0.76,1.88), (1.575,1.66,1.795,1.88), (1.575,1.66,1.795,1.88), (2.045,1.66,2.265,1.88), (2.045,1.66,2.265,1.88), (4.21,2.27,4.43,2.49), (4.21,2.27,4.43,2.49), (0.21,2.775,0.43,2.995), (0.21,2.775,0.43,2.995), (1.81,2.775,2.03,2.995), (1.81,2.775,2.03,2.995), (3.41,2.97,3.63,3.19), (3.41,2.97,3.63,3.19), (5.01,3.035,5.23,3.255), (5.01,3.035,5.23,3.255), (1.01,3.29,1.23,3.51), (1.01,3.29,1.23,3.51), (2.61,3.29,2.83,3.51), (2.61,3.29,2.83,3.51)])
R(gf180mcu_as_sc_mcu7t3v3_, metal1, [(0,-0.3,5.6,0.3), (0,-0.3,5.6,0.3), (0.205,0.3,0.435,0.69), (0.205,0.3,0.435,0.69), (3.405,0.3,3.635,0.69), (3.405,0.3,3.635,0.69), (5.005,0.3,5.235,0.69), (5.005,0.3,5.235,0.69), (1.68,1.025,4.49,1.255), (1.68,1.025,4.49,1.255), (4.145,1.255,4.435,2.62), (4.145,1.255,4.435,2.62), (4.735,1.565,5.125,2.31), (4.735,1.565,5.125,2.31), (2.86,1.57,3.265,1.93), (2.86,1.57,3.265,1.93), (0.455,1.59,0.875,1.955), (0.455,1.59,0.875,1.955), (1.38,1.59,2.46,1.95), (1.38,1.59,2.46,1.95), (2.86,1.93,3.09,2.31), (2.86,1.93,3.09,2.31), (0.645,1.955,0.875,2.31), (0.645,1.955,0.875,2.31), (0.645,2.31,3.09,2.54), (0.645,2.31,3.09,2.54), (0.205,2.695,0.435,2.77), (0.205,2.695,0.435,2.77), (0.205,2.77,3.635,3), (0.205,2.77,3.635,3), (5.005,2.97,5.235,3.16), (5.005,2.97,5.235,3.16), (0.205,3,0.435,3.08), (0.205,3,0.435,3.08), (3.405,3,3.635,3.16), (3.405,3,3.635,3.16), (3.405,3.16,5.235,3.39), (3.405,3.16,5.235,3.39), (1.005,3.23,1.235,3.62), (1.005,3.23,1.235,3.62), (2.605,3.23,2.835,3.62), (2.605,3.23,2.835,3.62), (0,3.62,5.6,4.22), (0,3.62,5.6,4.22)])
R(gf180mcu_as_sc_mcu7t3v3_, metal1_pin, [(0,-0.3,5.6,0.3), (0,-0.3,5.6,0.3), (4.145,1.025,4.435,2.62), (4.145,1.025,4.435,2.62), (4.735,1.565,5.125,2.31), (4.735,1.565,5.125,2.31), (0.455,1.59,0.875,1.955), (0.455,1.59,0.875,1.955), (1.38,1.59,2.46,1.95), (1.38,1.59,2.46,1.95), (0,3.62,5.6,4.22), (0,3.62,5.6,4.22)])
R(gf180mcu_as_sc_mcu7t3v3_, lvpwell, [(-0.43,-0.43,6.03,1.77), (-0.43,-0.43,6.03,1.77)])
R(gf180mcu_as_sc_mcu7t3v3_, lvpwell_10, [(0.05,-0.25,0.55,0.25), (0.05,-0.25,0.55,0.25)])
gf180mcu_as_sc_mcu7t3v3_.add(gdstk.Label('VDD', (2.8,3.92), layer=34, texttype=10))
gf180mcu_as_sc_mcu7t3v3_.add(gdstk.Label('VSS', (2.8,0), layer=34, texttype=10))
gf180mcu_as_sc_mcu7t3v3_.add(gdstk.Label('Y', (4.29,1.822), layer=34, texttype=10))
gf180mcu_as_sc_mcu7t3v3_.add(gdstk.Label('C', (4.93,1.937), layer=34, texttype=10))
gf180mcu_as_sc_mcu7t3v3_.add(gdstk.Label('B', (1.92,1.77), layer=34, texttype=10))
gf180mcu_as_sc_mcu7t3v3_.add(gdstk.Label('A', (0.665,1.772), layer=34, texttype=10))
gf180mcu_as_sc_mcu7t3v3_.add(gdstk.Label('VDD', (2.8,3.92), layer=34, texttype=10))
gf180mcu_as_sc_mcu7t3v3_.add(gdstk.Label('VSS', (2.8,0), layer=34, texttype=10))
gf180mcu_as_sc_mcu7t3v3_.add(gdstk.Label('Y', (4.29,1.822), layer=34, texttype=10))
gf180mcu_as_sc_mcu7t3v3_.add(gdstk.Label('C', (4.93,1.937), layer=34, texttype=10))
gf180mcu_as_sc_mcu7t3v3_.add(gdstk.Label('B', (1.92,1.77), layer=34, texttype=10))
gf180mcu_as_sc_mcu7t3v3_.add(gdstk.Label('A', (0.665,1.772), layer=34, texttype=10))
gf180mcu_as_sc_mcu7t3v3_.add(gdstk.Label('VNW', (0.3,3.92), layer=21, texttype=10))
gf180mcu_as_sc_mcu7t3v3_.add(gdstk.Label('VNW', (0.3,3.92), layer=21, texttype=10))
gf180mcu_as_sc_mcu7t3v3_.add(gdstk.Label('VPW', (0.3,0), layer=204, texttype=10))
gf180mcu_as_sc_mcu7t3v3_.add(gdstk.Label('VPW', (0.3,0), layer=204, texttype=10))

lib.write_gds('gf180mcu_as_sc_mcu7t3v3__aoi21_2.gds')
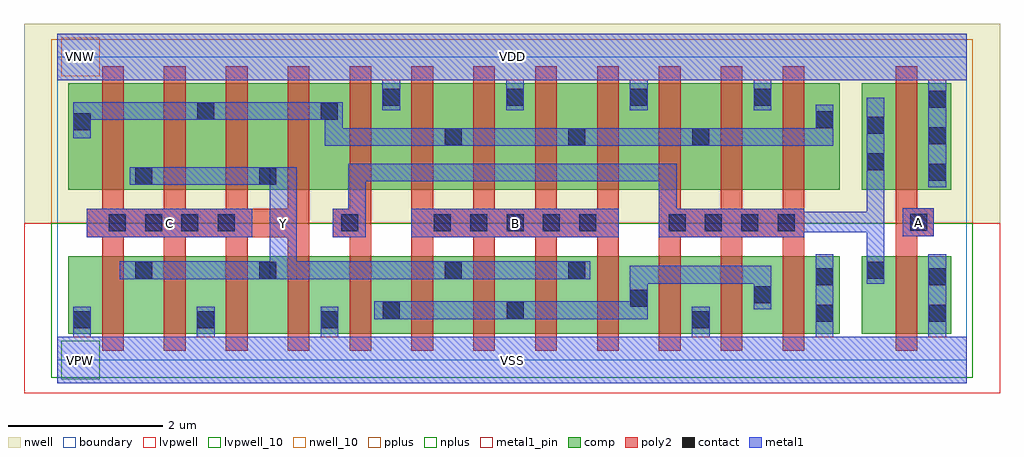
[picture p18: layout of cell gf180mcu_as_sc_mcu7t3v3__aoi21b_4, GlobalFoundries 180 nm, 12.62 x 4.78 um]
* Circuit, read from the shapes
.subckt gf180mcu_as_sc_mcu7t3v3__aoi21b_4 A B C VDD VNW VSS Y
XM1 Y C VSS VSUBS nfet_03v3 w=1u l=0.28u m=4
XM2 n1 n2 VSS VSUBS nfet_03v3 w=1u l=0.28u m=4
XM3 Y B n1 VSUBS nfet_03v3 w=1u l=0.28u m=4
XM4 VSS A n2 VSUBS nfet_03v3 w=1u l=0.28u
XM5 Y C n3 VNW pfet_03v3 w=1.38u l=0.28u m=4
XM6 VDD n2 n3 VNW pfet_03v3 w=1.38u l=0.28u m=4
XM7 n3 B VDD VNW pfet_03v3 w=1.38u l=0.28u m=4
XM8 VDD A n2 VNW pfet_03v3 w=1.38u l=0.28u
.ends

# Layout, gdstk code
import gdstk
lib = gdstk.Library(unit=1e-6, precision=1e-09)
def R(c, l, rs):  # rectangles x0, y0, x1, y1
    for r in rs: c.add(gdstk.rectangle(r[:2], r[2:], *l))
boundary = (0, 0)
nwell = (21, 0)
nwell_10 = (21, 10)
comp = (22, 0)
poly2 = (30, 0)
pplus = (31, 0)
nplus = (32, 0)
contact = (33, 0)
metal1 = (34, 0)
metal1_pin = (34, 10)
lvpwell = (204, 0)
lvpwell_10 = (204, 10)

gf180mcu_as_sc_mcu7t3v3_ = lib.new_cell('gf180mcu_as_sc_mcu7t3v3__aoi21b_4')
R(gf180mcu_as_sc_mcu7t3v3_, boundary, [(0,0,11.76,3.92), (0,0,11.76,3.92)])
R(gf180mcu_as_sc_mcu7t3v3_, nwell, [(-0.43,1.77,12.19,4.35), (-0.43,1.77,12.19,4.35)])
R(gf180mcu_as_sc_mcu7t3v3_, nwell_10, [(0.05,3.67,0.55,4.17), (0.05,3.67,0.55,4.17)])
R(gf180mcu_as_sc_mcu7t3v3_, comp, [(0.14,0.34,10.12,1.34), (0.14,0.34,10.12,1.34), (10.4,0.34,11.56,1.34), (10.4,0.34,11.56,1.34), (0.14,2.2,10.12,3.58), (0.14,2.2,10.12,3.58), (10.4,2.2,11.56,3.58), (10.4,2.2,11.56,3.58)])
R(gf180mcu_as_sc_mcu7t3v3_, poly2, [(0.58,0.12,0.86,1.59), (0.58,0.12,0.86,1.59), (1.38,0.12,1.66,1.59), (1.38,0.12,1.66,1.59), (2.18,0.12,2.46,1.59), (2.18,0.12,2.46,1.59), (2.98,0.12,3.26,1.59), (2.98,0.12,3.26,1.59), (3.78,0.12,4.06,1.59), (3.78,0.12,4.06,1.59), (4.58,0.12,4.86,1.59), (4.58,0.12,4.86,1.59), (5.38,0.12,5.66,1.59), (5.38,0.12,5.66,1.59), (6.18,0.12,6.46,1.59), (6.18,0.12,6.46,1.59), (6.98,0.12,7.26,1.59), (6.98,0.12,7.26,1.59), (7.78,0.12,8.06,1.59), (7.78,0.12,8.06,1.59), (8.58,0.12,8.86,1.59), (8.58,0.12,8.86,1.59), (9.38,0.12,9.66,1.59), (9.38,0.12,9.66,1.59), (10.84,0.12,11.12,1.6), (10.84,0.12,11.12,1.6), (0.38,1.59,3.26,1.955), (0.38,1.59,3.26,1.955), (3.565,1.59,4.06,1.955), (3.565,1.59,4.06,1.955), (4.58,1.59,7.26,1.955), (4.58,1.59,7.26,1.955), (7.78,1.59,9.66,1.955), (7.78,1.59,9.66,1.955), (10.84,1.6,11.335,1.965), (10.84,1.6,11.335,1.965), (0.58,1.955,0.86,3.8), (0.58,1.955,0.86,3.8), (1.38,1.955,1.66,3.8), (1.38,1.955,1.66,3.8), (2.18,1.955,2.46,3.8), (2.18,1.955,2.46,3.8), (2.98,1.955,3.26,3.8), (2.98,1.955,3.26,3.8), (3.78,1.955,4.06,3.8), (3.78,1.955,4.06,3.8), (4.58,1.955,4.86,3.8), (4.58,1.955,4.86,3.8), (5.38,1.955,5.66,3.8), (5.38,1.955,5.66,3.8), (6.18,1.955,6.46,3.8), (6.18,1.955,6.46,3.8), (6.98,1.955,7.26,3.8), (6.98,1.955,7.26,3.8), (7.78,1.955,8.06,3.8), (7.78,1.955,8.06,3.8), (8.58,1.955,8.86,3.8), (8.58,1.955,8.86,3.8), (9.38,1.955,9.66,3.8), (9.38,1.955,9.66,3.8), (10.84,1.965,11.12,3.8), (10.84,1.965,11.12,3.8)])
R(gf180mcu_as_sc_mcu7t3v3_, pplus, [(-0.08,1.77,11.84,4.15), (-0.08,1.77,11.84,4.15), (0.35,1.97,9.89,2.04), (0.35,1.97,9.89,2.04), (10.61,1.97,11.35,2.04), (10.61,1.97,11.35,2.04), (-0.02,2.04,11.72,3.74), (-0.02,2.04,11.72,3.74), (0.35,3.74,9.89,3.81), (0.35,3.74,9.89,3.81), (10.61,3.74,11.35,3.81), (10.61,3.74,11.35,3.81)])
R(gf180mcu_as_sc_mcu7t3v3_, nplus, [(-0.08,-0.23,11.84,1.77), (-0.08,-0.23,11.84,1.77), (-0.08,-0.23,11.84,1.77), (-0.08,-0.23,11.84,1.77)])
R(gf180mcu_as_sc_mcu7t3v3_, contact, [(0.21,0.41,0.43,0.63), (0.21,0.41,0.43,0.63), (1.81,0.41,2.03,0.63), (1.81,0.41,2.03,0.63), (3.41,0.41,3.63,0.63), (3.41,0.41,3.63,0.63), (8.21,0.41,8.43,0.63), (8.21,0.41,8.43,0.63), (9.81,0.495,10.03,0.715), (9.81,0.495,10.03,0.715), (11.27,0.495,11.49,0.715), (11.27,0.495,11.49,0.715), (4.21,0.535,4.43,0.755), (4.21,0.535,4.43,0.755), (5.81,0.535,6.03,0.755), (5.81,0.535,6.03,0.755), (7.41,0.69,7.63,0.91), (7.41,0.69,7.63,0.91), (9.01,0.735,9.23,0.955), (9.01,0.735,9.23,0.955), (9.81,0.965,10.03,1.185), (9.81,0.965,10.03,1.185), (11.27,0.965,11.49,1.185), (11.27,0.965,11.49,1.185), (1.01,1.05,1.23,1.27), (1.01,1.05,1.23,1.27), (2.61,1.05,2.83,1.27), (2.61,1.05,2.83,1.27), (5.01,1.05,5.23,1.27), (5.01,1.05,5.23,1.27), (6.61,1.05,6.83,1.27), (6.61,1.05,6.83,1.27), (10.47,1.05,10.69,1.27), (10.47,1.05,10.69,1.27), (0.665,1.665,0.885,1.885), (0.665,1.665,0.885,1.885), (1.135,1.665,1.355,1.885), (1.135,1.665,1.355,1.885), (1.605,1.665,1.825,1.885), (1.605,1.665,1.825,1.885), (2.075,1.665,2.295,1.885), (2.075,1.665,2.295,1.885), (3.67,1.665,3.89,1.885), (3.67,1.665,3.89,1.885), (4.87,1.665,5.09,1.885), (4.87,1.665,5.09,1.885), (5.34,1.665,5.56,1.885), (5.34,1.665,5.56,1.885), (5.81,1.665,6.03,1.885), (5.81,1.665,6.03,1.885), (6.28,1.665,6.5,1.885), (6.28,1.665,6.5,1.885), (6.75,1.665,6.97,1.885), (6.75,1.665,6.97,1.885), (7.905,1.665,8.125,1.885), (7.905,1.665,8.125,1.885), (8.375,1.665,8.595,1.885), (8.375,1.665,8.595,1.885), (8.845,1.665,9.065,1.885), (8.845,1.665,9.065,1.885), (9.315,1.665,9.535,1.885), (9.315,1.665,9.535,1.885), (11.03,1.67,11.25,1.89), (11.03,1.67,11.25,1.89), (1.01,2.27,1.23,2.49), (1.01,2.27,1.23,2.49), (2.61,2.27,2.83,2.49), (2.61,2.27,2.83,2.49), (11.27,2.32,11.49,2.54), (11.27,2.32,11.49,2.54), (10.47,2.455,10.69,2.675), (10.47,2.455,10.69,2.675), (5.01,2.775,5.23,2.995), (5.01,2.775,5.23,2.995), (6.61,2.775,6.83,2.995), (6.61,2.775,6.83,2.995), (8.21,2.775,8.43,2.995), (8.21,2.775,8.43,2.995), (11.27,2.79,11.49,3.01), (11.27,2.79,11.49,3.01), (10.47,2.925,10.69,3.145), (10.47,2.925,10.69,3.145), (0.21,2.97,0.43,3.19), (0.21,2.97,0.43,3.19), (9.81,3,10.03,3.22), (9.81,3,10.03,3.22), (1.81,3.11,2.03,3.33), (1.81,3.11,2.03,3.33), (3.41,3.11,3.63,3.33), (3.41,3.11,3.63,3.33), (11.27,3.26,11.49,3.48), (11.27,3.26,11.49,3.48), (4.21,3.29,4.43,3.51), (4.21,3.29,4.43,3.51), (5.81,3.29,6.03,3.51), (5.81,3.29,6.03,3.51), (7.41,3.29,7.63,3.51), (7.41,3.29,7.63,3.51), (9.01,3.29,9.23,3.51), (9.01,3.29,9.23,3.51)])
R(gf180mcu_as_sc_mcu7t3v3_, metal1, [(0,-0.3,11.76,0.3), (0,-0.3,11.76,0.3), (0.205,0.3,0.435,0.69), (0.205,0.3,0.435,0.69), (1.805,0.3,2.035,0.69), (1.805,0.3,2.035,0.69), (3.405,0.3,3.635,0.69), (3.405,0.3,3.635,0.69), (8.205,0.3,8.435,0.69), (8.205,0.3,8.435,0.69), (9.805,0.3,10.035,1.37), (9.805,0.3,10.035,1.37), (11.265,0.3,11.495,1.37), (11.265,0.3,11.495,1.37), (4.1,0.53,7.635,0.76), (4.1,0.53,7.635,0.76), (9.005,0.655,9.235,0.99), (9.005,0.655,9.235,0.99), (7.405,0.76,7.635,0.99), (7.405,0.76,7.635,0.99), (7.405,0.99,9.235,1.22), (7.405,0.99,9.235,1.22), (10.465,0.99,10.695,1.65), (10.465,0.99,10.695,1.65), (0.805,1.045,6.895,1.275), (0.805,1.045,6.895,1.275), (2.75,1.275,3.095,2.265), (2.75,1.275,3.095,2.265), (0.38,1.59,2.52,1.955), (0.38,1.59,2.52,1.955), (3.565,1.59,3.99,1.955), (3.565,1.59,3.99,1.955), (4.58,1.59,7.26,1.955), (4.58,1.59,7.26,1.955), (7.78,1.59,9.66,1.65), (7.78,1.59,9.66,1.65), (10.935,1.6,11.335,1.965), (10.935,1.6,11.335,1.965), (7.78,1.65,10.695,1.915), (7.78,1.65,10.695,1.915), (7.78,1.915,9.66,1.955), (7.78,1.915,9.66,1.955), (10.465,1.915,10.695,3.39), (10.465,1.915,10.695,3.39), (3.76,1.955,3.99,2.31), (3.76,1.955,3.99,2.31), (7.78,1.955,8.01,2.31), (7.78,1.955,8.01,2.31), (11.265,2.235,11.495,3.62), (11.265,2.235,11.495,3.62), (0.935,2.265,3.095,2.495), (0.935,2.265,3.095,2.495), (3.76,2.31,8.01,2.54), (3.76,2.31,8.01,2.54), (3.46,2.77,10.035,3), (3.46,2.77,10.035,3), (0.205,2.87,0.435,3.105), (0.205,2.87,0.435,3.105), (3.46,3,3.69,3.105), (3.46,3,3.69,3.105), (9.805,3,10.035,3.3), (9.805,3,10.035,3.3), (0.205,3.105,3.69,3.335), (0.205,3.105,3.69,3.335), (4.205,3.23,4.435,3.62), (4.205,3.23,4.435,3.62), (5.805,3.23,6.035,3.62), (5.805,3.23,6.035,3.62), (7.405,3.23,7.635,3.62), (7.405,3.23,7.635,3.62), (9.005,3.23,9.235,3.62), (9.005,3.23,9.235,3.62), (0,3.62,11.76,4.22), (0,3.62,11.76,4.22)])
R(gf180mcu_as_sc_mcu7t3v3_, metal1_pin, [(0,-0.3,11.76,0.3), (0,-0.3,11.76,0.3), (2.75,1.045,3.095,2.495), (2.75,1.045,3.095,2.495), (0.38,1.59,2.52,1.955), (0.38,1.59,2.52,1.955), (4.58,1.59,7.26,1.955), (4.58,1.59,7.26,1.955), (10.935,1.6,11.335,1.965), (10.935,1.6,11.335,1.965), (0,3.62,11.76,4.22), (0,3.62,11.76,4.22)])
R(gf180mcu_as_sc_mcu7t3v3_, lvpwell, [(-0.43,-0.43,12.19,1.77), (-0.43,-0.43,12.19,1.77)])
R(gf180mcu_as_sc_mcu7t3v3_, lvpwell_10, [(0.05,-0.25,0.55,0.25), (0.05,-0.25,0.55,0.25)])
gf180mcu_as_sc_mcu7t3v3_.add(gdstk.Label('VDD', (5.88,3.92), layer=34, texttype=10))
gf180mcu_as_sc_mcu7t3v3_.add(gdstk.Label('VSS', (5.88,0), layer=34, texttype=10))
gf180mcu_as_sc_mcu7t3v3_.add(gdstk.Label('Y', (2.922,1.77), layer=34, texttype=10))
gf180mcu_as_sc_mcu7t3v3_.add(gdstk.Label('C', (1.45,1.772), layer=34, texttype=10))
gf180mcu_as_sc_mcu7t3v3_.add(gdstk.Label('A', (11.135,1.782), layer=34, texttype=10))
gf180mcu_as_sc_mcu7t3v3_.add(gdstk.Label('B', (5.92,1.772), layer=34, texttype=10))
gf180mcu_as_sc_mcu7t3v3_.add(gdstk.Label('VDD', (5.88,3.92), layer=34, texttype=10))
gf180mcu_as_sc_mcu7t3v3_.add(gdstk.Label('VSS', (5.88,0), layer=34, texttype=10))
gf180mcu_as_sc_mcu7t3v3_.add(gdstk.Label('Y', (2.922,1.77), layer=34, texttype=10))
gf180mcu_as_sc_mcu7t3v3_.add(gdstk.Label('C', (1.45,1.772), layer=34, texttype=10))
gf180mcu_as_sc_mcu7t3v3_.add(gdstk.Label('A', (11.135,1.782), layer=34, texttype=10))
gf180mcu_as_sc_mcu7t3v3_.add(gdstk.Label('B', (5.92,1.772), layer=34, texttype=10))
gf180mcu_as_sc_mcu7t3v3_.add(gdstk.Label('VNW', (0.3,3.92), layer=21, texttype=10))
gf180mcu_as_sc_mcu7t3v3_.add(gdstk.Label('VNW', (0.3,3.92), layer=21, texttype=10))
gf180mcu_as_sc_mcu7t3v3_.add(gdstk.Label('VPW', (0.3,0), layer=204, texttype=10))
gf180mcu_as_sc_mcu7t3v3_.add(gdstk.Label('VPW', (0.3,0), layer=204, texttype=10))

lib.write_gds('gf180mcu_as_sc_mcu7t3v3__aoi21b_4.gds')
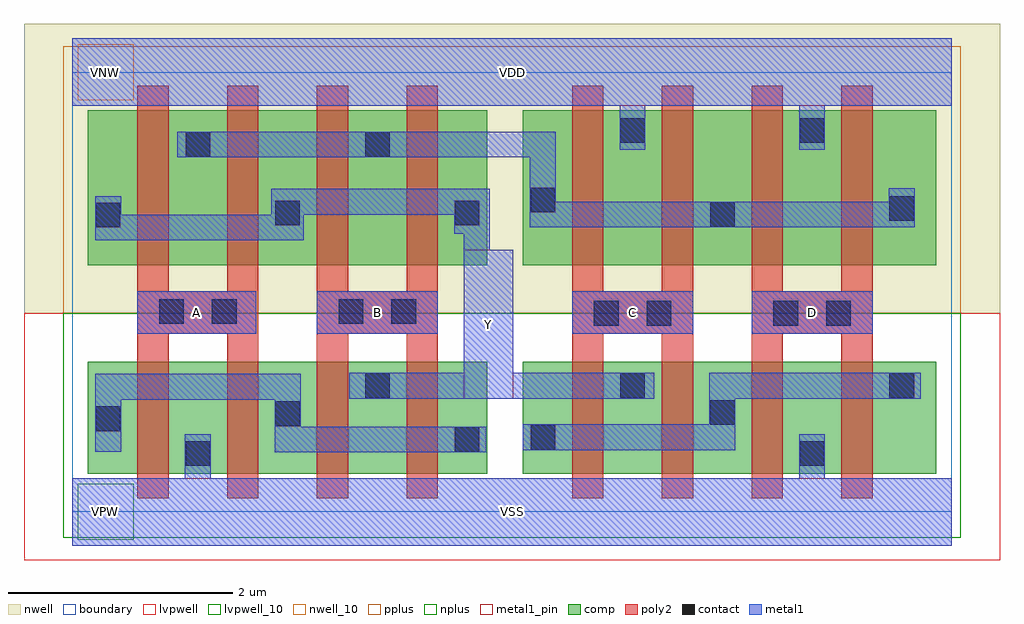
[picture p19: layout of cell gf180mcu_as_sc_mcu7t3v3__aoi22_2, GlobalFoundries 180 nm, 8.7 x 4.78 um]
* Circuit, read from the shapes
.subckt gf180mcu_as_sc_mcu7t3v3__aoi22_2 A B C D VDD VNW VSS Y
XM1 VSS A n1 VSUBS nfet_03v3 w=1u l=0.28u m=2
XM2 Y B n1 VSUBS nfet_03v3 w=1u l=0.28u m=2
XM3 Y C n2 VSUBS nfet_03v3 w=1u l=0.28u m=2
XM4 VSS D n2 VSUBS nfet_03v3 w=1u l=0.28u m=2
XM5 n3 A Y VNW pfet_03v3 w=1.38u l=0.28u m=2
XM6 n3 B Y VNW pfet_03v3 w=1.38u l=0.28u m=2
XM7 VDD C n3 VNW pfet_03v3 w=1.38u l=0.28u m=2
XM8 VDD D n3 VNW pfet_03v3 w=1.38u l=0.28u m=2
.ends

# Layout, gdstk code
import gdstk
lib = gdstk.Library(unit=1e-6, precision=1e-09)
def R(c, l, rs):  # rectangles x0, y0, x1, y1
    for r in rs: c.add(gdstk.rectangle(r[:2], r[2:], *l))
boundary = (0, 0)
nwell = (21, 0)
nwell_10 = (21, 10)
comp = (22, 0)
poly2 = (30, 0)
pplus = (31, 0)
nplus = (32, 0)
contact = (33, 0)
metal1 = (34, 0)
metal1_pin = (34, 10)
lvpwell = (204, 0)
lvpwell_10 = (204, 10)

gf180mcu_as_sc_mcu7t3v3_ = lib.new_cell('gf180mcu_as_sc_mcu7t3v3__aoi22_2')
R(gf180mcu_as_sc_mcu7t3v3_, boundary, [(0,0,7.84,3.92), (0,0,7.84,3.92)])
R(gf180mcu_as_sc_mcu7t3v3_, nwell, [(-0.43,1.77,8.27,4.35), (-0.43,1.77,8.27,4.35)])
R(gf180mcu_as_sc_mcu7t3v3_, nwell_10, [(0.05,3.67,0.55,4.17), (0.05,3.67,0.55,4.17)])
R(gf180mcu_as_sc_mcu7t3v3_, comp, [(0.14,0.34,3.7,1.34), (0.14,0.34,3.7,1.34), (4.015,0.34,7.7,1.34), (4.015,0.34,7.7,1.34), (0.14,2.2,3.7,3.58), (0.14,2.2,3.7,3.58), (4.015,2.2,7.7,3.58), (4.015,2.2,7.7,3.58)])
R(gf180mcu_as_sc_mcu7t3v3_, poly2, [(0.58,0.12,0.86,1.59), (0.58,0.12,0.86,1.59), (1.38,0.12,1.66,1.59), (1.38,0.12,1.66,1.59), (2.18,0.12,2.46,1.59), (2.18,0.12,2.46,1.59), (2.98,0.12,3.26,1.59), (2.98,0.12,3.26,1.59), (4.455,0.12,4.735,1.59), (4.455,0.12,4.735,1.59), (5.255,0.12,5.535,1.59), (5.255,0.12,5.535,1.59), (6.055,0.12,6.335,1.59), (6.055,0.12,6.335,1.59), (6.855,0.12,7.135,1.59), (6.855,0.12,7.135,1.59), (0.58,1.59,1.66,1.965), (0.58,1.59,1.66,1.965), (2.18,1.59,3.26,1.965), (2.18,1.59,3.26,1.965), (4.455,1.59,5.535,1.965), (4.455,1.59,5.535,1.965), (6.055,1.59,7.135,1.965), (6.055,1.59,7.135,1.965), (0.58,1.965,0.86,3.8), (0.58,1.965,0.86,3.8), (1.38,1.965,1.66,3.8), (1.38,1.965,1.66,3.8), (2.18,1.965,2.46,3.8), (2.18,1.965,2.46,3.8), (2.98,1.965,3.26,3.8), (2.98,1.965,3.26,3.8), (4.455,1.965,4.735,3.8), (4.455,1.965,4.735,3.8), (5.255,1.965,5.535,3.8), (5.255,1.965,5.535,3.8), (6.055,1.965,6.335,3.8), (6.055,1.965,6.335,3.8), (6.855,1.965,7.135,3.8), (6.855,1.965,7.135,3.8)])
R(gf180mcu_as_sc_mcu7t3v3_, pplus, [(-0.08,1.77,7.92,4.15), (-0.08,1.77,7.92,4.15), (0.35,1.97,3.49,2.04), (0.35,1.97,3.49,2.04), (4.225,1.97,7.365,2.04), (4.225,1.97,7.365,2.04), (-0.02,2.04,7.86,3.74), (-0.02,2.04,7.86,3.74), (0.35,3.74,3.49,3.81), (0.35,3.74,3.49,3.81), (4.225,3.74,7.365,3.81), (4.225,3.74,7.365,3.81)])
R(gf180mcu_as_sc_mcu7t3v3_, nplus, [(-0.08,-0.23,7.92,1.77), (-0.08,-0.23,7.92,1.77), (-0.08,-0.23,7.92,1.77), (-0.08,-0.23,7.92,1.77)])
R(gf180mcu_as_sc_mcu7t3v3_, contact, [(1.01,0.41,1.23,0.63), (1.01,0.41,1.23,0.63), (6.485,0.41,6.705,0.63), (6.485,0.41,6.705,0.63), (3.41,0.535,3.63,0.755), (3.41,0.535,3.63,0.755), (4.085,0.555,4.305,0.775), (4.085,0.555,4.305,0.775), (0.21,0.72,0.43,0.94), (0.21,0.72,0.43,0.94), (1.81,0.765,2.03,0.985), (1.81,0.765,2.03,0.985), (5.685,0.775,5.905,0.995), (5.685,0.775,5.905,0.995), (2.61,1.015,2.83,1.235), (2.61,1.015,2.83,1.235), (4.885,1.015,5.105,1.235), (4.885,1.015,5.105,1.235), (7.285,1.015,7.505,1.235), (7.285,1.015,7.505,1.235), (4.65,1.66,4.87,1.88), (4.65,1.66,4.87,1.88), (5.12,1.66,5.34,1.88), (5.12,1.66,5.34,1.88), (6.25,1.66,6.47,1.88), (6.25,1.66,6.47,1.88), (6.72,1.66,6.94,1.88), (6.72,1.66,6.94,1.88), (0.775,1.675,0.995,1.895), (0.775,1.675,0.995,1.895), (1.245,1.675,1.465,1.895), (1.245,1.675,1.465,1.895), (2.375,1.675,2.595,1.895), (2.375,1.675,2.595,1.895), (2.845,1.675,3.065,1.895), (2.845,1.675,3.065,1.895), (0.21,2.535,0.43,2.755), (0.21,2.535,0.43,2.755), (5.685,2.54,5.905,2.76), (5.685,2.54,5.905,2.76), (1.81,2.555,2.03,2.775), (1.81,2.555,2.03,2.775), (3.41,2.555,3.63,2.775), (3.41,2.555,3.63,2.775), (7.285,2.595,7.505,2.815), (7.285,2.595,7.505,2.815), (4.085,2.67,4.305,2.89), (4.085,2.67,4.305,2.89), (1.01,3.165,1.23,3.385), (1.01,3.165,1.23,3.385), (2.61,3.165,2.83,3.385), (2.61,3.165,2.83,3.385), (4.885,3.29,5.105,3.51), (4.885,3.29,5.105,3.51), (6.485,3.29,6.705,3.51), (6.485,3.29,6.705,3.51)])
R(gf180mcu_as_sc_mcu7t3v3_, metal1, [(0,-0.3,7.84,0.3), (0,-0.3,7.84,0.3), (1.005,0.3,1.235,0.69), (1.005,0.3,1.235,0.69), (6.48,0.3,6.71,0.69), (6.48,0.3,6.71,0.69), (1.805,0.53,3.69,0.76), (1.805,0.53,3.69,0.76), (0.205,0.535,0.435,1), (0.205,0.535,0.435,1), (4.015,0.55,5.91,0.78), (4.015,0.55,5.91,0.78), (1.805,0.76,2.035,1), (1.805,0.76,2.035,1), (5.68,0.78,5.91,1.01), (5.68,0.78,5.91,1.01), (0.205,1,2.035,1.23), (0.205,1,2.035,1.23), (2.47,1.01,5.19,1.24), (2.47,1.01,5.19,1.24), (5.68,1.01,7.565,1.24), (5.68,1.01,7.565,1.24), (3.49,1.24,3.93,2.335), (3.49,1.24,3.93,2.335), (0.58,1.59,1.64,1.965), (0.58,1.59,1.64,1.965), (2.18,1.59,3.26,1.965), (2.18,1.59,3.26,1.965), (4.455,1.59,5.535,1.965), (4.455,1.59,5.535,1.965), (6.055,1.59,7.135,1.965), (6.055,1.59,7.135,1.965), (3.49,2.335,3.72,2.48), (3.49,2.335,3.72,2.48), (0.205,2.42,2.065,2.65), (0.205,2.42,2.065,2.65), (3.405,2.48,3.72,2.65), (3.405,2.48,3.72,2.65), (4.08,2.535,7.51,2.765), (4.08,2.535,7.51,2.765), (0.205,2.65,0.435,2.815), (0.205,2.65,0.435,2.815), (1.775,2.65,3.72,2.88), (1.775,2.65,3.72,2.88), (4.08,2.765,4.31,3.16), (4.08,2.765,4.31,3.16), (7.28,2.765,7.51,2.885), (7.28,2.765,7.51,2.885), (0.935,3.16,4.31,3.39), (0.935,3.16,4.31,3.39), (4.88,3.23,5.11,3.62), (4.88,3.23,5.11,3.62), (6.48,3.23,6.71,3.62), (6.48,3.23,6.71,3.62), (0,3.62,7.84,4.22), (0,3.62,7.84,4.22)])
R(gf180mcu_as_sc_mcu7t3v3_, metal1_pin, [(0,-0.3,7.84,0.3), (0,-0.3,7.84,0.3), (3.49,1.01,3.93,2.335), (3.49,1.01,3.93,2.335), (0.58,1.59,1.64,1.965), (0.58,1.59,1.64,1.965), (2.18,1.59,3.26,1.965), (2.18,1.59,3.26,1.965), (4.455,1.59,5.535,1.965), (4.455,1.59,5.535,1.965), (6.055,1.59,7.135,1.965), (6.055,1.59,7.135,1.965), (0,3.62,7.84,4.22), (0,3.62,7.84,4.22)])
R(gf180mcu_as_sc_mcu7t3v3_, lvpwell, [(-0.43,-0.43,8.27,1.77), (-0.43,-0.43,8.27,1.77)])
R(gf180mcu_as_sc_mcu7t3v3_, lvpwell_10, [(0.05,-0.25,0.55,0.25), (0.05,-0.25,0.55,0.25)])
gf180mcu_as_sc_mcu7t3v3_.add(gdstk.Label('VDD', (3.92,3.92), layer=34, texttype=10))
gf180mcu_as_sc_mcu7t3v3_.add(gdstk.Label('VSS', (3.92,0), layer=34, texttype=10))
gf180mcu_as_sc_mcu7t3v3_.add(gdstk.Label('Y', (3.71,1.672), layer=34, texttype=10))
gf180mcu_as_sc_mcu7t3v3_.add(gdstk.Label('A', (1.11,1.777), layer=34, texttype=10))
gf180mcu_as_sc_mcu7t3v3_.add(gdstk.Label('B', (2.72,1.777), layer=34, texttype=10))
gf180mcu_as_sc_mcu7t3v3_.add(gdstk.Label('C', (4.995,1.777), layer=34, texttype=10))
gf180mcu_as_sc_mcu7t3v3_.add(gdstk.Label('D', (6.595,1.777), layer=34, texttype=10))
gf180mcu_as_sc_mcu7t3v3_.add(gdstk.Label('VDD', (3.92,3.92), layer=34, texttype=10))
gf180mcu_as_sc_mcu7t3v3_.add(gdstk.Label('VSS', (3.92,0), layer=34, texttype=10))
gf180mcu_as_sc_mcu7t3v3_.add(gdstk.Label('Y', (3.71,1.672), layer=34, texttype=10))
gf180mcu_as_sc_mcu7t3v3_.add(gdstk.Label('A', (1.11,1.777), layer=34, texttype=10))
gf180mcu_as_sc_mcu7t3v3_.add(gdstk.Label('B', (2.72,1.777), layer=34, texttype=10))
gf180mcu_as_sc_mcu7t3v3_.add(gdstk.Label('C', (4.995,1.777), layer=34, texttype=10))
gf180mcu_as_sc_mcu7t3v3_.add(gdstk.Label('D', (6.595,1.777), layer=34, texttype=10))
gf180mcu_as_sc_mcu7t3v3_.add(gdstk.Label('VNW', (0.3,3.92), layer=21, texttype=10))
gf180mcu_as_sc_mcu7t3v3_.add(gdstk.Label('VNW', (0.3,3.92), layer=21, texttype=10))
gf180mcu_as_sc_mcu7t3v3_.add(gdstk.Label('VPW', (0.3,0), layer=204, texttype=10))
gf180mcu_as_sc_mcu7t3v3_.add(gdstk.Label('VPW', (0.3,0), layer=204, texttype=10))

lib.write_gds('gf180mcu_as_sc_mcu7t3v3__aoi22_2.gds')
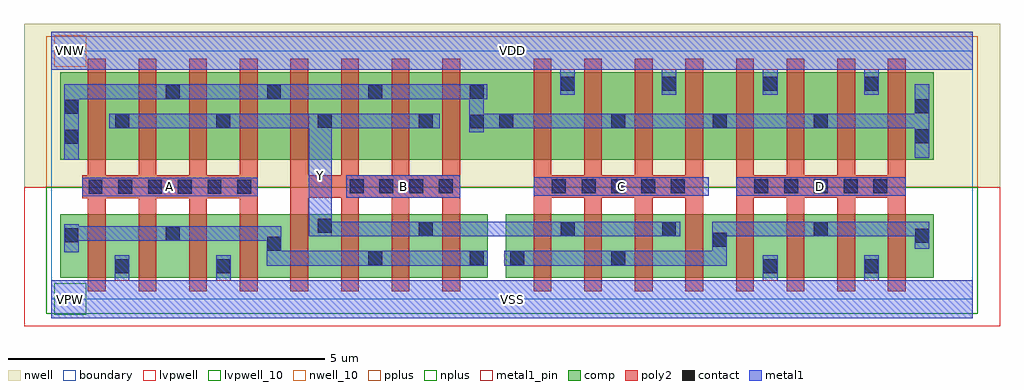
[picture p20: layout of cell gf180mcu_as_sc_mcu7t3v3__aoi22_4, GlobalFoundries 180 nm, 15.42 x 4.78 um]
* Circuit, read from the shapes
.subckt gf180mcu_as_sc_mcu7t3v3__aoi22_4 A B C D VDD VNW VSS Y
XM1 VSS A n1 VSUBS nfet_03v3 w=1u l=0.28u m=4
XM2 Y B n1 VSUBS nfet_03v3 w=1u l=0.28u m=4
XM3 Y C n2 VSUBS nfet_03v3 w=1u l=0.28u m=4
XM4 VSS D n2 VSUBS nfet_03v3 w=1u l=0.28u m=4
XM5 Y A n3 VNW pfet_03v3 w=1.38u l=0.28u m=4
XM6 Y B n3 VNW pfet_03v3 w=1.38u l=0.28u m=4
XM7 VDD C n3 VNW pfet_03v3 w=1.38u l=0.28u m=4
XM8 VDD D n3 VNW pfet_03v3 w=1.38u l=0.28u m=4
.ends

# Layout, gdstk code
import gdstk
lib = gdstk.Library(unit=1e-6, precision=1e-09)
def R(c, l, rs):  # rectangles x0, y0, x1, y1
    for r in rs: c.add(gdstk.rectangle(r[:2], r[2:], *l))
boundary = (0, 0)
nwell = (21, 0)
nwell_10 = (21, 10)
comp = (22, 0)
poly2 = (30, 0)
pplus = (31, 0)
nplus = (32, 0)
contact = (33, 0)
metal1 = (34, 0)
metal1_pin = (34, 10)
lvpwell = (204, 0)
lvpwell_10 = (204, 10)

gf180mcu_as_sc_mcu7t3v3_ = lib.new_cell('gf180mcu_as_sc_mcu7t3v3__aoi22_4')
R(gf180mcu_as_sc_mcu7t3v3_, boundary, [(0,0,14.56,3.92), (0,0,14.56,3.92)])
R(gf180mcu_as_sc_mcu7t3v3_, nwell, [(-0.43,1.77,14.99,4.35), (-0.43,1.77,14.99,4.35)])
R(gf180mcu_as_sc_mcu7t3v3_, nwell_10, [(0.05,3.67,0.55,4.17), (0.05,3.67,0.55,4.17)])
R(gf180mcu_as_sc_mcu7t3v3_, comp, [(0.14,0.34,6.9,1.34), (0.14,0.34,6.9,1.34), (7.18,0.34,13.94,1.34), (7.18,0.34,13.94,1.34), (0.14,2.2,13.94,3.58), (0.14,2.2,13.94,3.58)])
R(gf180mcu_as_sc_mcu7t3v3_, poly2, [(0.58,0.12,0.86,1.595), (0.58,0.12,0.86,1.595), (1.38,0.12,1.66,1.595), (1.38,0.12,1.66,1.595), (2.18,0.12,2.46,1.595), (2.18,0.12,2.46,1.595), (2.98,0.12,3.26,1.595), (2.98,0.12,3.26,1.595), (3.78,0.12,4.06,1.6), (3.78,0.12,4.06,1.6), (4.58,0.12,4.86,1.6), (4.58,0.12,4.86,1.6), (5.38,0.12,5.66,1.6), (5.38,0.12,5.66,1.6), (6.18,0.12,6.46,1.6), (6.18,0.12,6.46,1.6), (7.62,0.12,7.9,1.6), (7.62,0.12,7.9,1.6), (8.42,0.12,8.7,1.6), (8.42,0.12,8.7,1.6), (9.22,0.12,9.5,1.6), (9.22,0.12,9.5,1.6), (10.02,0.12,10.3,1.6), (10.02,0.12,10.3,1.6), (10.82,0.12,11.1,1.6), (10.82,0.12,11.1,1.6), (11.62,0.12,11.9,1.6), (11.62,0.12,11.9,1.6), (12.42,0.12,12.7,1.6), (12.42,0.12,12.7,1.6), (13.22,0.12,13.5,1.6), (13.22,0.12,13.5,1.6), (0.49,1.595,3.26,1.955), (0.49,1.595,3.26,1.955), (3.78,1.6,6.46,1.96), (3.78,1.6,6.46,1.96), (7.62,1.6,10.3,1.96), (7.62,1.6,10.3,1.96), (10.82,1.6,13.5,1.96), (10.82,1.6,13.5,1.96), (0.58,1.955,0.86,3.8), (0.58,1.955,0.86,3.8), (1.38,1.955,1.66,3.8), (1.38,1.955,1.66,3.8), (2.18,1.955,2.46,3.8), (2.18,1.955,2.46,3.8), (2.98,1.955,3.26,3.8), (2.98,1.955,3.26,3.8), (3.78,1.96,4.06,3.8), (3.78,1.96,4.06,3.8), (4.58,1.96,4.86,3.8), (4.58,1.96,4.86,3.8), (5.38,1.96,5.66,3.8), (5.38,1.96,5.66,3.8), (6.18,1.96,6.46,3.8), (6.18,1.96,6.46,3.8), (7.62,1.96,7.9,3.8), (7.62,1.96,7.9,3.8), (8.42,1.96,8.7,3.8), (8.42,1.96,8.7,3.8), (9.22,1.96,9.5,3.8), (9.22,1.96,9.5,3.8), (10.02,1.96,10.3,3.8), (10.02,1.96,10.3,3.8), (10.82,1.96,11.1,3.8), (10.82,1.96,11.1,3.8), (11.62,1.96,11.9,3.8), (11.62,1.96,11.9,3.8), (12.42,1.96,12.7,3.8), (12.42,1.96,12.7,3.8), (13.22,1.96,13.5,3.8), (13.22,1.96,13.5,3.8)])
R(gf180mcu_as_sc_mcu7t3v3_, pplus, [(-0.08,1.77,14.64,4.15), (-0.08,1.77,14.64,4.15), (0.35,1.97,6.69,2.04), (0.35,1.97,6.69,2.04), (7.39,1.97,13.73,2.04), (7.39,1.97,13.73,2.04), (-0.02,2.04,14.1,3.74), (-0.02,2.04,14.1,3.74), (0.35,3.74,6.69,3.81), (0.35,3.74,6.69,3.81), (7.39,3.74,13.73,3.81), (7.39,3.74,13.73,3.81)])
R(gf180mcu_as_sc_mcu7t3v3_, nplus, [(-0.08,-0.23,14.64,1.77), (-0.08,-0.23,14.64,1.77), (-0.08,-0.23,14.64,1.77), (-0.08,-0.23,14.64,1.77)])
R(gf180mcu_as_sc_mcu7t3v3_, contact, [(1.01,0.41,1.23,0.63), (1.01,0.41,1.23,0.63), (2.61,0.41,2.83,0.63), (2.61,0.41,2.83,0.63), (11.25,0.41,11.47,0.63), (11.25,0.41,11.47,0.63), (12.85,0.41,13.07,0.63), (12.85,0.41,13.07,0.63), (5.01,0.535,5.23,0.755), (5.01,0.535,5.23,0.755), (6.61,0.535,6.83,0.755), (6.61,0.535,6.83,0.755), (7.25,0.535,7.47,0.755), (7.25,0.535,7.47,0.755), (8.85,0.535,9.07,0.755), (8.85,0.535,9.07,0.755), (3.41,0.765,3.63,0.985), (3.41,0.765,3.63,0.985), (10.45,0.825,10.67,1.045), (10.45,0.825,10.67,1.045), (13.65,0.89,13.87,1.11), (13.65,0.89,13.87,1.11), (0.21,0.9,0.43,1.12), (0.21,0.9,0.43,1.12), (1.81,0.925,2.03,1.145), (1.81,0.925,2.03,1.145), (5.81,0.995,6.03,1.215), (5.81,0.995,6.03,1.215), (8.05,0.995,8.27,1.215), (8.05,0.995,8.27,1.215), (9.65,0.995,9.87,1.215), (9.65,0.995,9.87,1.215), (12.05,0.995,12.27,1.215), (12.05,0.995,12.27,1.215), (4.21,1.05,4.43,1.27), (4.21,1.05,4.43,1.27), (0.59,1.665,0.81,1.885), (0.59,1.665,0.81,1.885), (1.06,1.665,1.28,1.885), (1.06,1.665,1.28,1.885), (1.53,1.665,1.75,1.885), (1.53,1.665,1.75,1.885), (2,1.665,2.22,1.885), (2,1.665,2.22,1.885), (2.47,1.665,2.69,1.885), (2.47,1.665,2.69,1.885), (2.94,1.665,3.16,1.885), (2.94,1.665,3.16,1.885), (4.715,1.67,4.935,1.89), (4.715,1.67,4.935,1.89), (5.185,1.67,5.405,1.89), (5.185,1.67,5.405,1.89), (5.655,1.67,5.875,1.89), (5.655,1.67,5.875,1.89), (6.125,1.67,6.345,1.89), (6.125,1.67,6.345,1.89), (7.91,1.67,8.13,1.89), (7.91,1.67,8.13,1.89), (8.38,1.67,8.6,1.89), (8.38,1.67,8.6,1.89), (8.85,1.67,9.07,1.89), (8.85,1.67,9.07,1.89), (9.32,1.67,9.54,1.89), (9.32,1.67,9.54,1.89), (9.79,1.67,10.01,1.89), (9.79,1.67,10.01,1.89), (11.11,1.67,11.33,1.89), (11.11,1.67,11.33,1.89), (11.58,1.67,11.8,1.89), (11.58,1.67,11.8,1.89), (12.05,1.67,12.27,1.89), (12.05,1.67,12.27,1.89), (12.52,1.67,12.74,1.89), (12.52,1.67,12.74,1.89), (12.99,1.67,13.21,1.89), (12.99,1.67,13.21,1.89), (0.21,2.455,0.43,2.675), (0.21,2.455,0.43,2.675), (13.65,2.465,13.87,2.685), (13.65,2.465,13.87,2.685), (6.61,2.695,6.83,2.915), (6.61,2.695,6.83,2.915), (1.01,2.705,1.23,2.925), (1.01,2.705,1.23,2.925), (2.61,2.705,2.83,2.925), (2.61,2.705,2.83,2.925), (4.21,2.705,4.43,2.925), (4.21,2.705,4.43,2.925), (5.81,2.705,6.03,2.925), (5.81,2.705,6.03,2.925), (7.08,2.705,7.3,2.925), (7.08,2.705,7.3,2.925), (8.85,2.705,9.07,2.925), (8.85,2.705,9.07,2.925), (10.45,2.705,10.67,2.925), (10.45,2.705,10.67,2.925), (12.05,2.705,12.27,2.925), (12.05,2.705,12.27,2.925), (0.21,2.925,0.43,3.145), (0.21,2.925,0.43,3.145), (13.65,2.935,13.87,3.155), (13.65,2.935,13.87,3.155), (1.81,3.165,2.03,3.385), (1.81,3.165,2.03,3.385), (3.41,3.165,3.63,3.385), (3.41,3.165,3.63,3.385), (5.01,3.165,5.23,3.385), (5.01,3.165,5.23,3.385), (6.61,3.165,6.83,3.385), (6.61,3.165,6.83,3.385), (8.05,3.29,8.27,3.51), (8.05,3.29,8.27,3.51), (9.65,3.29,9.87,3.51), (9.65,3.29,9.87,3.51), (11.25,3.29,11.47,3.51), (11.25,3.29,11.47,3.51), (12.85,3.29,13.07,3.51), (12.85,3.29,13.07,3.51)])
R(gf180mcu_as_sc_mcu7t3v3_, metal1, [(0,-0.3,14.56,0.3), (0,-0.3,14.56,0.3), (1.005,0.3,1.235,0.69), (1.005,0.3,1.235,0.69), (2.605,0.3,2.835,0.69), (2.605,0.3,2.835,0.69), (11.245,0.3,11.475,0.69), (11.245,0.3,11.475,0.69), (12.845,0.3,13.075,0.69), (12.845,0.3,13.075,0.69), (3.405,0.53,6.895,0.76), (3.405,0.53,6.895,0.76), (7.16,0.53,10.675,0.76), (7.16,0.53,10.675,0.76), (0.205,0.74,0.435,0.92), (0.205,0.74,0.435,0.92), (3.405,0.76,3.635,0.92), (3.405,0.76,3.635,0.92), (10.445,0.76,10.675,0.99), (10.445,0.76,10.675,0.99), (13.645,0.795,13.875,0.99), (13.645,0.795,13.875,0.99), (0.205,0.92,3.635,1.15), (0.205,0.92,3.635,1.15), (4.07,0.99,9.94,1.22), (4.07,0.99,9.94,1.22), (10.445,0.99,13.875,1.22), (10.445,0.99,13.875,1.22), (0.205,1.15,0.435,1.185), (0.205,1.15,0.435,1.185), (4.07,1.22,4.435,2.7), (4.07,1.22,4.435,2.7), (4.665,1.6,6.46,1.96), (4.665,1.6,6.46,1.96), (0.49,1.625,3.26,1.92), (0.49,1.625,3.26,1.92), (7.62,1.63,10.39,1.925), (7.62,1.63,10.39,1.925), (10.82,1.63,13.5,1.925), (10.82,1.63,13.5,1.925), (0.205,2.2,0.435,3.16), (0.205,2.2,0.435,3.16), (13.645,2.235,13.875,2.7), (13.645,2.235,13.875,2.7), (6.605,2.635,6.835,2.7), (6.605,2.635,6.835,2.7), (0.915,2.7,6.135,2.93), (0.915,2.7,6.135,2.93), (6.605,2.7,13.875,2.93), (6.605,2.7,13.875,2.93), (6.605,2.93,6.835,3.16), (6.605,2.93,6.835,3.16), (13.645,2.93,13.875,3.39), (13.645,2.93,13.875,3.39), (0.205,3.16,6.89,3.39), (0.205,3.16,6.89,3.39), (8.045,3.23,8.275,3.62), (8.045,3.23,8.275,3.62), (9.645,3.23,9.875,3.62), (9.645,3.23,9.875,3.62), (11.245,3.23,11.475,3.62), (11.245,3.23,11.475,3.62), (12.845,3.23,13.075,3.62), (12.845,3.23,13.075,3.62), (0,3.62,14.56,4.22), (0,3.62,14.56,4.22)])
R(gf180mcu_as_sc_mcu7t3v3_, metal1_pin, [(0,-0.3,14.56,0.3), (0,-0.3,14.56,0.3), (4.07,0.99,4.435,2.93), (4.07,0.99,4.435,2.93), (4.665,1.6,6.46,1.96), (4.665,1.6,6.46,1.96), (0.49,1.625,3.26,1.92), (0.49,1.625,3.26,1.92), (7.62,1.63,10.39,1.925), (7.62,1.63,10.39,1.925), (10.82,1.63,13.5,1.925), (10.82,1.63,13.5,1.925), (0,3.62,14.56,4.22), (0,3.62,14.56,4.22)])
R(gf180mcu_as_sc_mcu7t3v3_, lvpwell, [(-0.43,-0.43,14.99,1.77), (-0.43,-0.43,14.99,1.77)])
R(gf180mcu_as_sc_mcu7t3v3_, lvpwell_10, [(0.05,-0.25,0.55,0.25), (0.05,-0.25,0.55,0.25)])
gf180mcu_as_sc_mcu7t3v3_.add(gdstk.Label('VDD', (7.28,3.92), layer=34, texttype=10))
gf180mcu_as_sc_mcu7t3v3_.add(gdstk.Label('VSS', (7.28,0), layer=34, texttype=10))
gf180mcu_as_sc_mcu7t3v3_.add(gdstk.Label('Y', (4.252,1.96), layer=34, texttype=10))
gf180mcu_as_sc_mcu7t3v3_.add(gdstk.Label('A', (1.875,1.772), layer=34, texttype=10))
gf180mcu_as_sc_mcu7t3v3_.add(gdstk.Label('B', (5.562,1.78), layer=34, texttype=10))
gf180mcu_as_sc_mcu7t3v3_.add(gdstk.Label('C', (9.005,1.777), layer=34, texttype=10))
gf180mcu_as_sc_mcu7t3v3_.add(gdstk.Label('D', (12.16,1.777), layer=34, texttype=10))
gf180mcu_as_sc_mcu7t3v3_.add(gdstk.Label('VDD', (7.28,3.92), layer=34, texttype=10))
gf180mcu_as_sc_mcu7t3v3_.add(gdstk.Label('VSS', (7.28,0), layer=34, texttype=10))
gf180mcu_as_sc_mcu7t3v3_.add(gdstk.Label('Y', (4.252,1.96), layer=34, texttype=10))
gf180mcu_as_sc_mcu7t3v3_.add(gdstk.Label('A', (1.875,1.772), layer=34, texttype=10))
gf180mcu_as_sc_mcu7t3v3_.add(gdstk.Label('B', (5.562,1.78), layer=34, texttype=10))
gf180mcu_as_sc_mcu7t3v3_.add(gdstk.Label('C', (9.005,1.777), layer=34, texttype=10))
gf180mcu_as_sc_mcu7t3v3_.add(gdstk.Label('D', (12.16,1.777), layer=34, texttype=10))
gf180mcu_as_sc_mcu7t3v3_.add(gdstk.Label('VNW', (0.3,3.92), layer=21, texttype=10))
gf180mcu_as_sc_mcu7t3v3_.add(gdstk.Label('VNW', (0.3,3.92), layer=21, texttype=10))
gf180mcu_as_sc_mcu7t3v3_.add(gdstk.Label('VPW', (0.3,0), layer=204, texttype=10))
gf180mcu_as_sc_mcu7t3v3_.add(gdstk.Label('VPW', (0.3,0), layer=204, texttype=10))

lib.write_gds('gf180mcu_as_sc_mcu7t3v3__aoi22_4.gds')
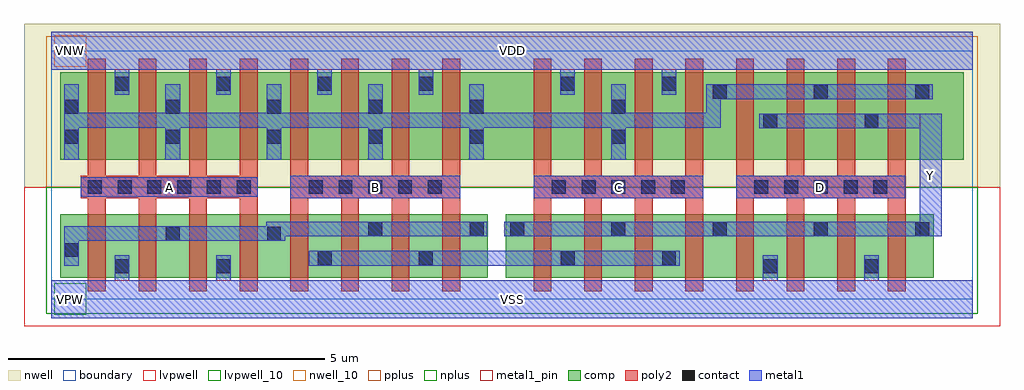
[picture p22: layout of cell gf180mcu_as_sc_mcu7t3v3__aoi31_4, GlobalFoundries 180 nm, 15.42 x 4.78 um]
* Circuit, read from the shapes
.subckt gf180mcu_as_sc_mcu7t3v3__aoi31_4 A B C D VDD VNW VSS Y
XM1 VSS A n1 VSUBS nfet_03v3 w=1u l=0.28u m=4
XM2 n2 B n1 VSUBS nfet_03v3 w=1u l=0.28u m=4
XM3 n2 C Y VSUBS nfet_03v3 w=1u l=0.28u m=4
XM4 VSS D Y VSUBS nfet_03v3 w=1u l=0.28u m=4
XM5 VDD A n3 VNW pfet_03v3 w=1.38u l=0.28u m=4
XM6 VDD B n3 VNW pfet_03v3 w=1.38u l=0.28u m=4
XM7 VDD C n3 VNW pfet_03v3 w=1.38u l=0.28u m=4
XM8 Y D n3 VNW pfet_03v3 w=1.38u l=0.28u m=4
.ends

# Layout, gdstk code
import gdstk
lib = gdstk.Library(unit=1e-6, precision=1e-09)
def R(c, l, rs):  # rectangles x0, y0, x1, y1
    for r in rs: c.add(gdstk.rectangle(r[:2], r[2:], *l))
boundary = (0, 0)
nwell = (21, 0)
nwell_10 = (21, 10)
comp = (22, 0)
poly2 = (30, 0)
pplus = (31, 0)
nplus = (32, 0)
contact = (33, 0)
metal1 = (34, 0)
metal1_pin = (34, 10)
lvpwell = (204, 0)
lvpwell_10 = (204, 10)

gf180mcu_as_sc_mcu7t3v3_ = lib.new_cell('gf180mcu_as_sc_mcu7t3v3__aoi31_4')
R(gf180mcu_as_sc_mcu7t3v3_, boundary, [(0,0,14.56,3.92), (0,0,14.56,3.92)])
R(gf180mcu_as_sc_mcu7t3v3_, nwell, [(-0.43,1.77,14.99,4.35), (-0.43,1.77,14.99,4.35)])
R(gf180mcu_as_sc_mcu7t3v3_, nwell_10, [(0.05,3.67,0.55,4.17), (0.05,3.67,0.55,4.17)])
R(gf180mcu_as_sc_mcu7t3v3_, comp, [(0.14,0.34,6.9,1.34), (0.14,0.34,6.9,1.34), (7.18,0.34,13.94,1.34), (7.18,0.34,13.94,1.34), (0.14,2.2,14.42,3.58), (0.14,2.2,14.42,3.58)])
R(gf180mcu_as_sc_mcu7t3v3_, poly2, [(0.58,0.12,0.86,1.59), (0.58,0.12,0.86,1.59), (1.38,0.12,1.66,1.59), (1.38,0.12,1.66,1.59), (2.18,0.12,2.46,1.59), (2.18,0.12,2.46,1.59), (2.98,0.12,3.26,1.59), (2.98,0.12,3.26,1.59), (3.78,0.12,4.06,1.59), (3.78,0.12,4.06,1.59), (4.58,0.12,4.86,1.59), (4.58,0.12,4.86,1.59), (5.38,0.12,5.66,1.59), (5.38,0.12,5.66,1.59), (6.18,0.12,6.46,1.59), (6.18,0.12,6.46,1.59), (7.62,0.12,7.9,1.59), (7.62,0.12,7.9,1.59), (8.42,0.12,8.7,1.59), (8.42,0.12,8.7,1.59), (9.22,0.12,9.5,1.59), (9.22,0.12,9.5,1.59), (10.02,0.12,10.3,1.59), (10.02,0.12,10.3,1.59), (10.82,0.12,11.1,1.59), (10.82,0.12,11.1,1.59), (11.62,0.12,11.9,1.59), (11.62,0.12,11.9,1.59), (12.42,0.12,12.7,1.59), (12.42,0.12,12.7,1.59), (13.22,0.12,13.5,1.59), (13.22,0.12,13.5,1.59), (0.47,1.59,3.265,1.95), (0.47,1.59,3.265,1.95), (3.78,1.59,6.46,1.95), (3.78,1.59,6.46,1.95), (7.62,1.59,10.3,1.95), (7.62,1.59,10.3,1.95), (10.82,1.59,13.5,1.95), (10.82,1.59,13.5,1.95), (0.58,1.95,0.86,3.8), (0.58,1.95,0.86,3.8), (1.38,1.95,1.66,3.8), (1.38,1.95,1.66,3.8), (2.18,1.95,2.46,3.8), (2.18,1.95,2.46,3.8), (2.98,1.95,3.26,3.8), (2.98,1.95,3.26,3.8), (3.78,1.95,4.06,3.8), (3.78,1.95,4.06,3.8), (4.58,1.95,4.86,3.8), (4.58,1.95,4.86,3.8), (5.38,1.95,5.66,3.8), (5.38,1.95,5.66,3.8), (6.18,1.95,6.46,3.8), (6.18,1.95,6.46,3.8), (7.62,1.95,7.9,3.8), (7.62,1.95,7.9,3.8), (8.42,1.95,8.7,3.8), (8.42,1.95,8.7,3.8), (9.22,1.95,9.5,3.8), (9.22,1.95,9.5,3.8), (10.02,1.95,10.3,3.8), (10.02,1.95,10.3,3.8), (10.82,1.95,11.1,3.8), (10.82,1.95,11.1,3.8), (11.62,1.95,11.9,3.8), (11.62,1.95,11.9,3.8), (12.42,1.95,12.7,3.8), (12.42,1.95,12.7,3.8), (13.22,1.95,13.5,3.8), (13.22,1.95,13.5,3.8)])
R(gf180mcu_as_sc_mcu7t3v3_, pplus, [(-0.08,1.77,14.64,4.15), (-0.08,1.77,14.64,4.15), (0.35,1.97,6.69,2.04), (0.35,1.97,6.69,2.04), (7.39,1.97,13.73,2.04), (7.39,1.97,13.73,2.04), (-0.02,2.04,14.58,3.74), (-0.02,2.04,14.58,3.74), (0.35,3.74,6.69,3.81), (0.35,3.74,6.69,3.81), (7.39,3.74,13.73,3.81), (7.39,3.74,13.73,3.81)])
R(gf180mcu_as_sc_mcu7t3v3_, nplus, [(-0.08,-0.23,14.64,1.77), (-0.08,-0.23,14.64,1.77), (-0.08,-0.23,14.64,1.77), (-0.08,-0.23,14.64,1.77)])
R(gf180mcu_as_sc_mcu7t3v3_, contact, [(1.01,0.41,1.23,0.63), (1.01,0.41,1.23,0.63), (2.61,0.41,2.83,0.63), (2.61,0.41,2.83,0.63), (11.25,0.41,11.47,0.63), (11.25,0.41,11.47,0.63), (12.85,0.41,13.07,0.63), (12.85,0.41,13.07,0.63), (4.21,0.535,4.43,0.755), (4.21,0.535,4.43,0.755), (5.81,0.535,6.03,0.755), (5.81,0.535,6.03,0.755), (8.05,0.535,8.27,0.755), (8.05,0.535,8.27,0.755), (9.65,0.535,9.87,0.755), (9.65,0.535,9.87,0.755), (0.21,0.665,0.43,0.885), (0.21,0.665,0.43,0.885), (1.81,0.925,2.03,1.145), (1.81,0.925,2.03,1.145), (3.41,0.925,3.63,1.145), (3.41,0.925,3.63,1.145), (5.01,0.995,5.23,1.215), (5.01,0.995,5.23,1.215), (6.61,0.995,6.83,1.215), (6.61,0.995,6.83,1.215), (7.25,0.995,7.47,1.215), (7.25,0.995,7.47,1.215), (8.85,0.995,9.07,1.215), (8.85,0.995,9.07,1.215), (10.45,0.995,10.67,1.215), (10.45,0.995,10.67,1.215), (12.05,0.995,12.27,1.215), (12.05,0.995,12.27,1.215), (13.65,0.995,13.87,1.215), (13.65,0.995,13.87,1.215), (0.58,1.66,0.8,1.88), (0.58,1.66,0.8,1.88), (1.05,1.66,1.27,1.88), (1.05,1.66,1.27,1.88), (1.52,1.66,1.74,1.88), (1.52,1.66,1.74,1.88), (1.99,1.66,2.21,1.88), (1.99,1.66,2.21,1.88), (2.46,1.66,2.68,1.88), (2.46,1.66,2.68,1.88), (2.93,1.66,3.15,1.88), (2.93,1.66,3.15,1.88), (4.07,1.66,4.29,1.88), (4.07,1.66,4.29,1.88), (4.54,1.66,4.76,1.88), (4.54,1.66,4.76,1.88), (5.01,1.66,5.23,1.88), (5.01,1.66,5.23,1.88), (5.48,1.66,5.7,1.88), (5.48,1.66,5.7,1.88), (5.95,1.66,6.17,1.88), (5.95,1.66,6.17,1.88), (7.91,1.66,8.13,1.88), (7.91,1.66,8.13,1.88), (8.38,1.66,8.6,1.88), (8.38,1.66,8.6,1.88), (8.85,1.66,9.07,1.88), (8.85,1.66,9.07,1.88), (9.32,1.66,9.54,1.88), (9.32,1.66,9.54,1.88), (9.79,1.66,10.01,1.88), (9.79,1.66,10.01,1.88), (11.11,1.66,11.33,1.88), (11.11,1.66,11.33,1.88), (11.58,1.66,11.8,1.88), (11.58,1.66,11.8,1.88), (12.05,1.66,12.27,1.88), (12.05,1.66,12.27,1.88), (12.52,1.66,12.74,1.88), (12.52,1.66,12.74,1.88), (12.99,1.66,13.21,1.88), (12.99,1.66,13.21,1.88), (0.21,2.455,0.43,2.675), (0.21,2.455,0.43,2.675), (1.81,2.455,2.03,2.675), (1.81,2.455,2.03,2.675), (3.41,2.455,3.63,2.675), (3.41,2.455,3.63,2.675), (5.01,2.455,5.23,2.675), (5.01,2.455,5.23,2.675), (6.61,2.455,6.83,2.675), (6.61,2.455,6.83,2.675), (8.85,2.455,9.07,2.675), (8.85,2.455,9.07,2.675), (11.25,2.705,11.47,2.925), (11.25,2.705,11.47,2.925), (12.85,2.705,13.07,2.925), (12.85,2.705,13.07,2.925), (0.21,2.925,0.43,3.145), (0.21,2.925,0.43,3.145), (1.81,2.925,2.03,3.145), (1.81,2.925,2.03,3.145), (3.41,2.925,3.63,3.145), (3.41,2.925,3.63,3.145), (5.01,2.925,5.23,3.145), (5.01,2.925,5.23,3.145), (6.61,2.925,6.83,3.145), (6.61,2.925,6.83,3.145), (8.85,2.925,9.07,3.145), (8.85,2.925,9.07,3.145), (10.45,3.165,10.67,3.385), (10.45,3.165,10.67,3.385), (12.05,3.165,12.27,3.385), (12.05,3.165,12.27,3.385), (13.65,3.165,13.87,3.385), (13.65,3.165,13.87,3.385), (1.01,3.29,1.23,3.51), (1.01,3.29,1.23,3.51), (2.61,3.29,2.83,3.51), (2.61,3.29,2.83,3.51), (4.21,3.29,4.43,3.51), (4.21,3.29,4.43,3.51), (5.81,3.29,6.03,3.51), (5.81,3.29,6.03,3.51), (8.05,3.29,8.27,3.51), (8.05,3.29,8.27,3.51), (9.65,3.29,9.87,3.51), (9.65,3.29,9.87,3.51)])
R(gf180mcu_as_sc_mcu7t3v3_, metal1, [(0,-0.3,14.56,0.3), (0,-0.3,14.56,0.3), (1.005,0.3,1.235,0.69), (1.005,0.3,1.235,0.69), (2.605,0.3,2.835,0.69), (2.605,0.3,2.835,0.69), (11.245,0.3,11.475,0.69), (11.245,0.3,11.475,0.69), (12.845,0.3,13.075,0.69), (12.845,0.3,13.075,0.69), (0.205,0.53,0.435,0.92), (0.205,0.53,0.435,0.92), (4.07,0.53,9.93,0.76), (4.07,0.53,9.93,0.76), (0.205,0.92,3.7,0.99), (0.205,0.92,3.7,0.99), (0.205,0.99,6.89,1.15), (0.205,0.99,6.89,1.15), (7.155,0.99,14.07,1.22), (7.155,0.99,14.07,1.22), (3.4,1.15,6.89,1.22), (3.4,1.15,6.89,1.22), (13.725,1.22,14.07,2.7), (13.725,1.22,14.07,2.7), (3.78,1.59,6.46,1.95), (3.78,1.59,6.46,1.95), (7.62,1.59,10.3,1.95), (7.62,1.59,10.3,1.95), (10.82,1.59,13.495,1.95), (10.82,1.59,13.495,1.95), (0.47,1.615,3.265,1.925), (0.47,1.615,3.265,1.925), (0.205,2.2,0.435,2.71), (0.205,2.2,0.435,2.71), (1.805,2.2,2.035,2.71), (1.805,2.2,2.035,2.71), (3.405,2.2,3.635,2.71), (3.405,2.2,3.635,2.71), (5.005,2.2,5.235,2.71), (5.005,2.2,5.235,2.71), (6.605,2.2,6.835,2.71), (6.605,2.2,6.835,2.71), (8.845,2.2,9.075,2.71), (8.845,2.2,9.075,2.71), (11.185,2.7,14.07,2.93), (11.185,2.7,14.07,2.93), (0.205,2.71,10.58,2.94), (0.205,2.71,10.58,2.94), (0.205,2.94,0.435,3.39), (0.205,2.94,0.435,3.39), (1.805,2.94,2.035,3.39), (1.805,2.94,2.035,3.39), (3.405,2.94,3.635,3.39), (3.405,2.94,3.635,3.39), (5.005,2.94,5.235,3.39), (5.005,2.94,5.235,3.39), (6.605,2.94,6.835,3.39), (6.605,2.94,6.835,3.39), (8.845,2.94,9.075,3.39), (8.845,2.94,9.075,3.39), (10.35,2.94,10.58,3.16), (10.35,2.94,10.58,3.16), (10.35,3.16,13.93,3.39), (10.35,3.16,13.93,3.39), (1.005,3.23,1.235,3.62), (1.005,3.23,1.235,3.62), (2.605,3.23,2.835,3.62), (2.605,3.23,2.835,3.62), (4.205,3.23,4.435,3.62), (4.205,3.23,4.435,3.62), (5.805,3.23,6.035,3.62), (5.805,3.23,6.035,3.62), (8.045,3.23,8.275,3.62), (8.045,3.23,8.275,3.62), (9.645,3.23,9.875,3.62), (9.645,3.23,9.875,3.62), (0,3.62,14.56,4.22), (0,3.62,14.56,4.22)])
R(gf180mcu_as_sc_mcu7t3v3_, metal1_pin, [(0,-0.3,14.56,0.3), (0,-0.3,14.56,0.3), (13.725,0.99,14.07,2.93), (13.725,0.99,14.07,2.93), (3.78,1.59,6.46,1.95), (3.78,1.59,6.46,1.95), (7.62,1.59,10.3,1.95), (7.62,1.59,10.3,1.95), (10.82,1.59,13.495,1.95), (10.82,1.59,13.495,1.95), (0.47,1.615,3.265,1.925), (0.47,1.615,3.265,1.925), (0,3.62,14.56,4.22), (0,3.62,14.56,4.22)])
R(gf180mcu_as_sc_mcu7t3v3_, lvpwell, [(-0.43,-0.43,14.99,1.77), (-0.43,-0.43,14.99,1.77)])
R(gf180mcu_as_sc_mcu7t3v3_, lvpwell_10, [(0.05,-0.25,0.55,0.25), (0.05,-0.25,0.55,0.25)])
gf180mcu_as_sc_mcu7t3v3_.add(gdstk.Label('VDD', (7.28,3.92), layer=34, texttype=10))
gf180mcu_as_sc_mcu7t3v3_.add(gdstk.Label('VSS', (7.28,0), layer=34, texttype=10))
gf180mcu_as_sc_mcu7t3v3_.add(gdstk.Label('A', (1.867,1.77), layer=34, texttype=10))
gf180mcu_as_sc_mcu7t3v3_.add(gdstk.Label('B', (5.12,1.77), layer=34, texttype=10))
gf180mcu_as_sc_mcu7t3v3_.add(gdstk.Label('C', (8.96,1.77), layer=34, texttype=10))
gf180mcu_as_sc_mcu7t3v3_.add(gdstk.Label('D', (12.157,1.77), layer=34, texttype=10))
gf180mcu_as_sc_mcu7t3v3_.add(gdstk.Label('Y', (13.897,1.96), layer=34, texttype=10))
gf180mcu_as_sc_mcu7t3v3_.add(gdstk.Label('VDD', (7.28,3.92), layer=34, texttype=10))
gf180mcu_as_sc_mcu7t3v3_.add(gdstk.Label('VSS', (7.28,0), layer=34, texttype=10))
gf180mcu_as_sc_mcu7t3v3_.add(gdstk.Label('A', (1.867,1.77), layer=34, texttype=10))
gf180mcu_as_sc_mcu7t3v3_.add(gdstk.Label('B', (5.12,1.77), layer=34, texttype=10))
gf180mcu_as_sc_mcu7t3v3_.add(gdstk.Label('C', (8.96,1.77), layer=34, texttype=10))
gf180mcu_as_sc_mcu7t3v3_.add(gdstk.Label('D', (12.157,1.77), layer=34, texttype=10))
gf180mcu_as_sc_mcu7t3v3_.add(gdstk.Label('Y', (13.897,1.96), layer=34, texttype=10))
gf180mcu_as_sc_mcu7t3v3_.add(gdstk.Label('VNW', (0.3,3.92), layer=21, texttype=10))
gf180mcu_as_sc_mcu7t3v3_.add(gdstk.Label('VNW', (0.3,3.92), layer=21, texttype=10))
gf180mcu_as_sc_mcu7t3v3_.add(gdstk.Label('VPW', (0.3,0), layer=204, texttype=10))
gf180mcu_as_sc_mcu7t3v3_.add(gdstk.Label('VPW', (0.3,0), layer=204, texttype=10))

lib.write_gds('gf180mcu_as_sc_mcu7t3v3__aoi31_4.gds')
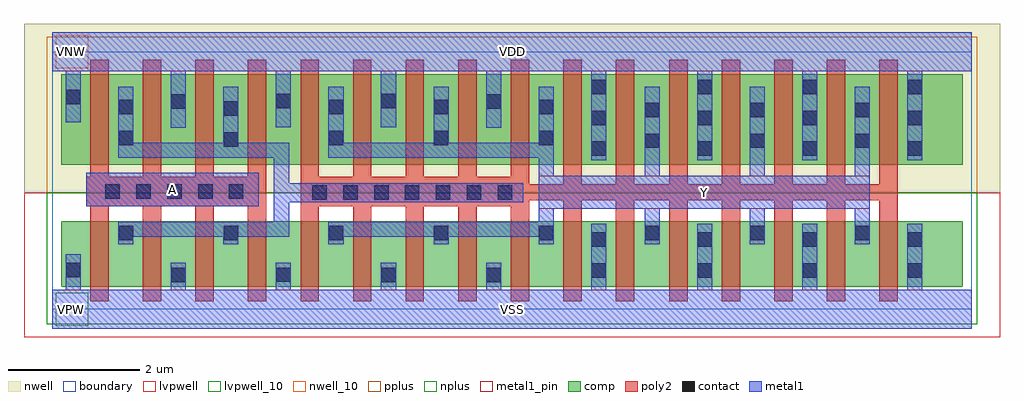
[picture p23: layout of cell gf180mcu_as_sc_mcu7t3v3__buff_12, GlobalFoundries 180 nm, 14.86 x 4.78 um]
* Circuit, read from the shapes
.subckt gf180mcu_as_sc_mcu7t3v3__buff_12 A VDD VNW VSS Y
XM1 n1 A VSS VSUBS nfet_03v3 w=1u l=0.28u m=4
XM2 Y n1 VSS VSUBS nfet_03v3 w=1u l=0.28u m=12
XM3 n1 A VDD VNW pfet_03v3 w=1.38u l=0.28u m=4
XM4 Y n1 VDD VNW pfet_03v3 w=1.38u l=0.28u m=12
.ends

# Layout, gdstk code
import gdstk
lib = gdstk.Library(unit=1e-6, precision=1e-09)
def R(c, l, rs):  # rectangles x0, y0, x1, y1
    for r in rs: c.add(gdstk.rectangle(r[:2], r[2:], *l))
boundary = (0, 0)
nwell = (21, 0)
nwell_10 = (21, 10)
comp = (22, 0)
poly2 = (30, 0)
pplus = (31, 0)
nplus = (32, 0)
contact = (33, 0)
metal1 = (34, 0)
metal1_pin = (34, 10)
lvpwell = (204, 0)
lvpwell_10 = (204, 10)

gf180mcu_as_sc_mcu7t3v3_ = lib.new_cell('gf180mcu_as_sc_mcu7t3v3__buff_12')
R(gf180mcu_as_sc_mcu7t3v3_, boundary, [(0,0,14,3.92), (0,0,14,3.92)])
R(gf180mcu_as_sc_mcu7t3v3_, nwell, [(-0.43,1.77,14.43,4.35), (-0.43,1.77,14.43,4.35)])
R(gf180mcu_as_sc_mcu7t3v3_, nwell_10, [(0.05,3.67,0.55,4.17), (0.05,3.67,0.55,4.17)])
R(gf180mcu_as_sc_mcu7t3v3_, comp, [(0.14,0.34,13.86,1.34), (0.14,0.34,13.86,1.34), (0.14,2.2,13.86,3.58), (0.14,2.2,13.86,3.58)])
R(gf180mcu_as_sc_mcu7t3v3_, poly2, [(0.58,0.12,0.86,1.57), (0.58,0.12,0.86,1.57), (1.38,0.12,1.66,1.57), (1.38,0.12,1.66,1.57), (2.18,0.12,2.46,1.57), (2.18,0.12,2.46,1.57), (2.98,0.12,3.26,1.57), (2.98,0.12,3.26,1.57), (3.78,0.12,4.06,1.57), (3.78,0.12,4.06,1.57), (4.58,0.12,4.86,1.57), (4.58,0.12,4.86,1.57), (5.38,0.12,5.66,1.57), (5.38,0.12,5.66,1.57), (6.18,0.12,6.46,1.57), (6.18,0.12,6.46,1.57), (6.98,0.12,7.26,1.57), (6.98,0.12,7.26,1.57), (7.78,0.12,8.06,1.66), (7.78,0.12,8.06,1.66), (8.58,0.12,8.86,1.66), (8.58,0.12,8.86,1.66), (9.395,0.12,9.675,1.66), (9.395,0.12,9.675,1.66), (10.195,0.12,10.475,1.66), (10.195,0.12,10.475,1.66), (10.995,0.12,11.275,1.66), (10.995,0.12,11.275,1.66), (11.795,0.12,12.075,1.66), (11.795,0.12,12.075,1.66), (12.595,0.12,12.875,1.66), (12.595,0.12,12.875,1.66), (0.515,1.57,3.26,2.015), (0.515,1.57,3.26,2.015), (3.78,1.57,7.26,1.66), (3.78,1.57,7.26,1.66), (3.78,1.66,12.875,1.905), (3.78,1.66,12.875,1.905), (3.78,1.905,7.26,2.015), (3.78,1.905,7.26,2.015), (7.78,1.905,8.06,3.8), (7.78,1.905,8.06,3.8), (8.58,1.905,8.86,3.8), (8.58,1.905,8.86,3.8), (9.395,1.905,9.675,3.8), (9.395,1.905,9.675,3.8), (10.195,1.905,10.475,3.8), (10.195,1.905,10.475,3.8), (10.995,1.905,11.275,3.8), (10.995,1.905,11.275,3.8), (11.795,1.905,12.075,3.8), (11.795,1.905,12.075,3.8), (12.595,1.905,12.875,3.8), (12.595,1.905,12.875,3.8), (0.58,2.015,0.86,3.8), (0.58,2.015,0.86,3.8), (1.38,2.015,1.66,3.8), (1.38,2.015,1.66,3.8), (2.18,2.015,2.46,3.8), (2.18,2.015,2.46,3.8), (2.98,2.015,3.26,3.8), (2.98,2.015,3.26,3.8), (3.78,2.015,4.06,3.8), (3.78,2.015,4.06,3.8), (4.58,2.015,4.86,3.8), (4.58,2.015,4.86,3.8), (5.38,2.015,5.66,3.8), (5.38,2.015,5.66,3.8), (6.18,2.015,6.46,3.8), (6.18,2.015,6.46,3.8), (6.98,2.015,7.26,3.8), (6.98,2.015,7.26,3.8)])
R(gf180mcu_as_sc_mcu7t3v3_, pplus, [(-0.08,1.77,14.08,4.15), (-0.08,1.77,14.08,4.15), (0.35,1.97,13.105,2.04), (0.35,1.97,13.105,2.04), (-0.02,2.04,14.02,3.74), (-0.02,2.04,14.02,3.74), (0.35,3.74,13.105,3.81), (0.35,3.74,13.105,3.81)])
R(gf180mcu_as_sc_mcu7t3v3_, nplus, [(-0.08,-0.23,14.08,1.77), (-0.08,-0.23,14.08,1.77), (-0.08,-0.23,14.08,1.77), (-0.08,-0.23,14.08,1.77)])
R(gf180mcu_as_sc_mcu7t3v3_, contact, [(1.81,0.41,2.03,0.63), (1.81,0.41,2.03,0.63), (5.01,0.41,5.23,0.63), (5.01,0.41,5.23,0.63), (6.61,0.41,6.83,0.63), (6.61,0.41,6.83,0.63), (3.41,0.415,3.63,0.635), (3.41,0.415,3.63,0.635), (8.21,0.48,8.43,0.7), (8.21,0.48,8.43,0.7), (9.825,0.48,10.045,0.7), (9.825,0.48,10.045,0.7), (11.425,0.48,11.645,0.7), (11.425,0.48,11.645,0.7), (13.025,0.48,13.245,0.7), (13.025,0.48,13.245,0.7), (0.21,0.485,0.43,0.705), (0.21,0.485,0.43,0.705), (8.21,0.95,8.43,1.17), (8.21,0.95,8.43,1.17), (9.825,0.95,10.045,1.17), (9.825,0.95,10.045,1.17), (11.425,0.95,11.645,1.17), (11.425,0.95,11.645,1.17), (13.025,0.95,13.245,1.17), (13.025,0.95,13.245,1.17), (1.01,1.05,1.23,1.27), (1.01,1.05,1.23,1.27), (2.61,1.05,2.83,1.27), (2.61,1.05,2.83,1.27), (4.21,1.05,4.43,1.27), (4.21,1.05,4.43,1.27), (5.81,1.05,6.03,1.27), (5.81,1.05,6.03,1.27), (7.41,1.05,7.63,1.27), (7.41,1.05,7.63,1.27), (9.025,1.05,9.245,1.27), (9.025,1.05,9.245,1.27), (10.625,1.05,10.845,1.27), (10.625,1.05,10.845,1.27), (12.225,1.05,12.445,1.27), (12.225,1.05,12.445,1.27), (3.96,1.665,4.18,1.885), (3.96,1.665,4.18,1.885), (4.43,1.665,4.65,1.885), (4.43,1.665,4.65,1.885), (4.9,1.665,5.12,1.885), (4.9,1.665,5.12,1.885), (5.37,1.665,5.59,1.885), (5.37,1.665,5.59,1.885), (5.84,1.665,6.06,1.885), (5.84,1.665,6.06,1.885), (6.31,1.665,6.53,1.885), (6.31,1.665,6.53,1.885), (6.78,1.665,7,1.885), (6.78,1.665,7,1.885), (0.81,1.685,1.03,1.905), (0.81,1.685,1.03,1.905), (1.28,1.685,1.5,1.905), (1.28,1.685,1.5,1.905), (1.75,1.685,1.97,1.905), (1.75,1.685,1.97,1.905), (2.22,1.685,2.44,1.905), (2.22,1.685,2.44,1.905), (2.69,1.685,2.91,1.905), (2.69,1.685,2.91,1.905), (8.21,2.335,8.43,2.555), (8.21,2.335,8.43,2.555), (9.825,2.335,10.045,2.555), (9.825,2.335,10.045,2.555), (11.425,2.335,11.645,2.555), (11.425,2.335,11.645,2.555), (13.025,2.335,13.245,2.555), (13.025,2.335,13.245,2.555), (9.025,2.455,9.245,2.675), (9.025,2.455,9.245,2.675), (10.625,2.455,10.845,2.675), (10.625,2.455,10.845,2.675), (12.225,2.455,12.445,2.675), (12.225,2.455,12.445,2.675), (2.61,2.475,2.83,2.695), (2.61,2.475,2.83,2.695), (1.01,2.5,1.23,2.72), (1.01,2.5,1.23,2.72), (4.21,2.5,4.43,2.72), (4.21,2.5,4.43,2.72), (5.81,2.5,6.03,2.72), (5.81,2.5,6.03,2.72), (7.41,2.5,7.63,2.72), (7.41,2.5,7.63,2.72), (8.21,2.805,8.43,3.025), (8.21,2.805,8.43,3.025), (9.825,2.805,10.045,3.025), (9.825,2.805,10.045,3.025), (11.425,2.805,11.645,3.025), (11.425,2.805,11.645,3.025), (13.025,2.805,13.245,3.025), (13.025,2.805,13.245,3.025), (9.025,2.925,9.245,3.145), (9.025,2.925,9.245,3.145), (10.625,2.925,10.845,3.145), (10.625,2.925,10.845,3.145), (12.225,2.925,12.445,3.145), (12.225,2.925,12.445,3.145), (2.61,2.945,2.83,3.165), (2.61,2.945,2.83,3.165), (1.01,2.97,1.23,3.19), (1.01,2.97,1.23,3.19), (4.21,2.97,4.43,3.19), (4.21,2.97,4.43,3.19), (5.81,2.97,6.03,3.19), (5.81,2.97,6.03,3.19), (7.41,2.97,7.63,3.19), (7.41,2.97,7.63,3.19), (1.81,3.05,2.03,3.27), (1.81,3.05,2.03,3.27), (6.61,3.055,6.83,3.275), (6.61,3.055,6.83,3.275), (3.41,3.06,3.63,3.28), (3.41,3.06,3.63,3.28), (5.01,3.06,5.23,3.28), (5.01,3.06,5.23,3.28), (0.21,3.12,0.43,3.34), (0.21,3.12,0.43,3.34), (8.21,3.275,8.43,3.495), (8.21,3.275,8.43,3.495), (9.825,3.275,10.045,3.495), (9.825,3.275,10.045,3.495), (11.425,3.275,11.645,3.495), (11.425,3.275,11.645,3.495), (13.025,3.275,13.245,3.495), (13.025,3.275,13.245,3.495)])
R(gf180mcu_as_sc_mcu7t3v3_, metal1, [(0,-0.3,14,0.3), (0,-0.3,14,0.3), (0.205,0.3,0.435,0.84), (0.205,0.3,0.435,0.84), (1.805,0.3,2.035,0.71), (1.805,0.3,2.035,0.71), (3.405,0.3,3.635,0.71), (3.405,0.3,3.635,0.71), (5.005,0.3,5.235,0.71), (5.005,0.3,5.235,0.71), (6.605,0.3,6.835,0.71), (6.605,0.3,6.835,0.71), (8.205,0.3,8.435,1.3), (8.205,0.3,8.435,1.3), (9.82,0.3,10.05,1.3), (9.82,0.3,10.05,1.3), (11.42,0.3,11.65,1.3), (11.42,0.3,11.65,1.3), (13.02,0.3,13.25,1.3), (13.02,0.3,13.25,1.3), (1.005,0.99,1.235,1.1), (1.005,0.99,1.235,1.1), (2.605,0.99,2.835,1.1), (2.605,0.99,2.835,1.1), (4.205,0.99,4.435,1.1), (4.205,0.99,4.435,1.1), (5.805,0.99,6.035,1.1), (5.805,0.99,6.035,1.1), (7.405,0.99,7.635,1.1), (7.405,0.99,7.635,1.1), (9.02,0.99,9.25,1.53), (9.02,0.99,9.25,1.53), (10.62,0.99,10.85,1.53), (10.62,0.99,10.85,1.53), (12.22,0.99,12.45,1.53), (12.22,0.99,12.45,1.53), (1.005,1.1,3.605,1.33), (1.005,1.1,3.605,1.33), (4.205,1.1,7.635,1.33), (4.205,1.1,7.635,1.33), (3.375,1.33,3.605,1.63), (3.375,1.33,3.605,1.63), (7.405,1.33,7.635,1.53), (7.405,1.33,7.635,1.53), (7.405,1.53,12.45,2.035), (7.405,1.53,12.45,2.035), (0.515,1.57,3.145,2.075), (0.515,1.57,3.145,2.075), (3.375,1.63,7.175,1.92), (3.375,1.63,7.175,1.92), (3.375,1.92,3.605,2.305), (3.375,1.92,3.605,2.305), (7.405,2.035,7.635,2.305), (7.405,2.035,7.635,2.305), (9.02,2.035,9.25,3.39), (9.02,2.035,9.25,3.39), (10.62,2.035,10.85,3.39), (10.62,2.035,10.85,3.39), (12.22,2.035,12.45,3.39), (12.22,2.035,12.45,3.39), (8.205,2.265,8.435,3.62), (8.205,2.265,8.435,3.62), (9.82,2.265,10.05,3.62), (9.82,2.265,10.05,3.62), (11.42,2.265,11.65,3.62), (11.42,2.265,11.65,3.62), (13.02,2.265,13.25,3.62), (13.02,2.265,13.25,3.62), (1.005,2.305,3.605,2.535), (1.005,2.305,3.605,2.535), (4.205,2.305,7.635,2.535), (4.205,2.305,7.635,2.535), (1.005,2.535,1.235,3.39), (1.005,2.535,1.235,3.39), (2.605,2.535,2.835,3.39), (2.605,2.535,2.835,3.39), (4.205,2.535,4.435,3.39), (4.205,2.535,4.435,3.39), (5.805,2.535,6.035,3.39), (5.805,2.535,6.035,3.39), (7.405,2.535,7.635,3.39), (7.405,2.535,7.635,3.39), (1.805,2.765,2.035,3.62), (1.805,2.765,2.035,3.62), (6.605,2.765,6.835,3.62), (6.605,2.765,6.835,3.62), (3.405,2.77,3.635,3.62), (3.405,2.77,3.635,3.62), (5.005,2.77,5.235,3.62), (5.005,2.77,5.235,3.62), (0.205,2.85,0.435,3.62), (0.205,2.85,0.435,3.62), (0,3.62,14,4.22), (0,3.62,14,4.22)])
R(gf180mcu_as_sc_mcu7t3v3_, metal1_pin, [(0,-0.3,14,0.3), (0,-0.3,14,0.3), (7.405,1.53,12.45,2.035), (7.405,1.53,12.45,2.035), (0.515,1.57,3.145,2.075), (0.515,1.57,3.145,2.075), (0,3.62,14,4.22), (0,3.62,14,4.22)])
R(gf180mcu_as_sc_mcu7t3v3_, lvpwell, [(-0.43,-0.43,14.43,1.77), (-0.43,-0.43,14.43,1.77)])
R(gf180mcu_as_sc_mcu7t3v3_, lvpwell_10, [(0.05,-0.25,0.55,0.25), (0.05,-0.25,0.55,0.25)])
gf180mcu_as_sc_mcu7t3v3_.add(gdstk.Label('VDD', (7,3.92), layer=34, texttype=10))
gf180mcu_as_sc_mcu7t3v3_.add(gdstk.Label('VSS', (7,0), layer=34, texttype=10))
gf180mcu_as_sc_mcu7t3v3_.add(gdstk.Label('A', (1.83,1.822), layer=34, texttype=10))
gf180mcu_as_sc_mcu7t3v3_.add(gdstk.Label('Y', (9.927,1.782), layer=34, texttype=10))
gf180mcu_as_sc_mcu7t3v3_.add(gdstk.Label('VDD', (7,3.92), layer=34, texttype=10))
gf180mcu_as_sc_mcu7t3v3_.add(gdstk.Label('VSS', (7,0), layer=34, texttype=10))
gf180mcu_as_sc_mcu7t3v3_.add(gdstk.Label('A', (1.83,1.822), layer=34, texttype=10))
gf180mcu_as_sc_mcu7t3v3_.add(gdstk.Label('Y', (9.927,1.782), layer=34, texttype=10))
gf180mcu_as_sc_mcu7t3v3_.add(gdstk.Label('VNW', (0.3,3.92), layer=21, texttype=10))
gf180mcu_as_sc_mcu7t3v3_.add(gdstk.Label('VNW', (0.3,3.92), layer=21, texttype=10))
gf180mcu_as_sc_mcu7t3v3_.add(gdstk.Label('VPW', (0.3,0), layer=204, texttype=10))
gf180mcu_as_sc_mcu7t3v3_.add(gdstk.Label('VPW', (0.3,0), layer=204, texttype=10))

lib.write_gds('gf180mcu_as_sc_mcu7t3v3__buff_12.gds')
